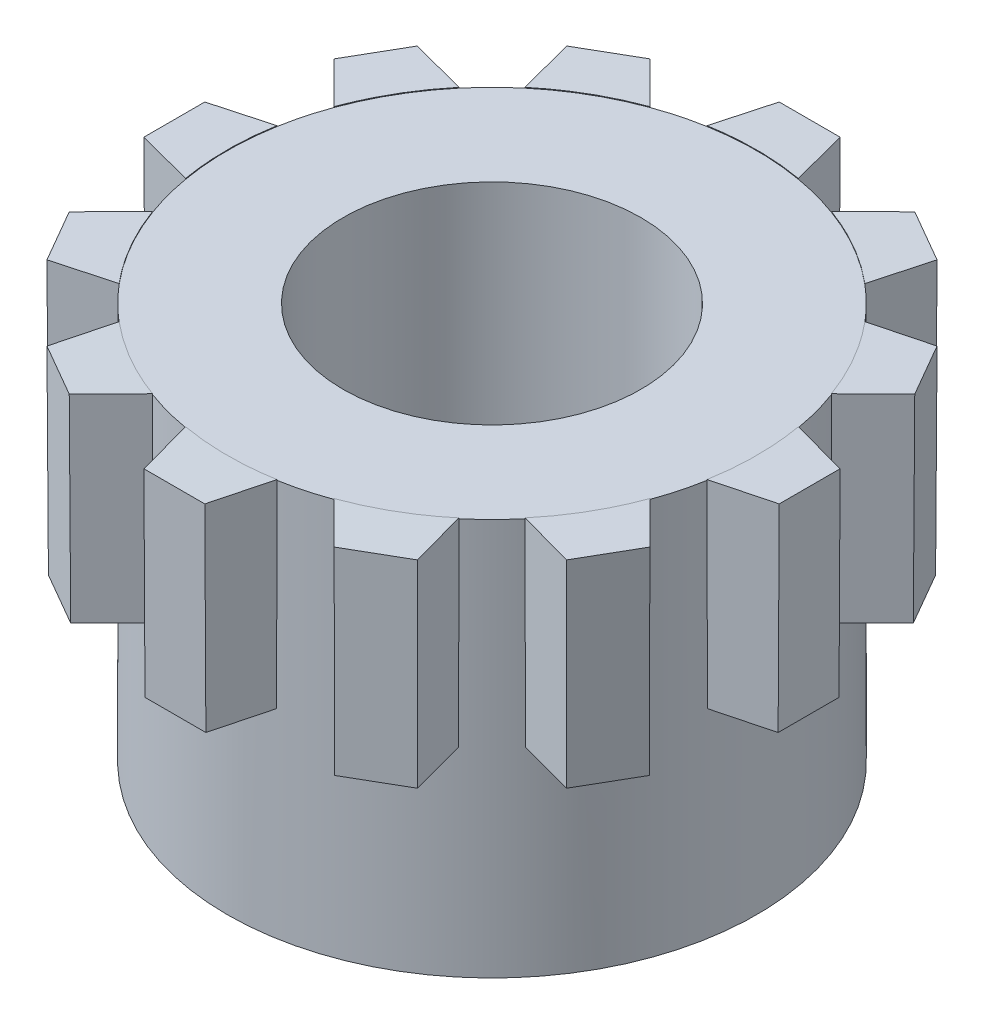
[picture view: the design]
ISO-10303-21;
HEADER;
FILE_DESCRIPTION(('STEP AP214'),'2;1');
FILE_NAME('part.step','',(''),(''),'','','');
FILE_SCHEMA(('AUTOMOTIVE_DESIGN { 1 0 10303 214 1 1 1 1 }'));
ENDSEC;
DATA;
#1=APPLICATION_CONTEXT('core data for automotive mechanical design processes');
#2=APPLICATION_PROTOCOL_DEFINITION('international standard','automotive_design',2000,#1);
#3=PRODUCT_CONTEXT('',#1,'mechanical');
#4=PRODUCT('Part','Part','',(#3));
#5=PRODUCT_RELATED_PRODUCT_CATEGORY('part','',(#4));
#6=PRODUCT_DEFINITION_FORMATION('','',#4);
#7=PRODUCT_DEFINITION_CONTEXT('part definition',#1,'design');
#8=PRODUCT_DEFINITION('design','',#6,#7);
#9=PRODUCT_DEFINITION_SHAPE('','',#8);
#10=(LENGTH_UNIT() NAMED_UNIT(*) SI_UNIT(.MILLI.,.METRE.));
#11=(NAMED_UNIT(*) PLANE_ANGLE_UNIT() SI_UNIT($,.RADIAN.));
#12=(NAMED_UNIT(*) SI_UNIT($,.STERADIAN.) SOLID_ANGLE_UNIT());
#13=UNCERTAINTY_MEASURE_WITH_UNIT(LENGTH_MEASURE(1.E-05),#10,'distance_accuracy_value','');
#14=(GEOMETRIC_REPRESENTATION_CONTEXT(3) GLOBAL_UNCERTAINTY_ASSIGNED_CONTEXT((#13)) GLOBAL_UNIT_ASSIGNED_CONTEXT((#10,
#11,#12)) REPRESENTATION_CONTEXT('',''));
#15=CARTESIAN_POINT('',(0.,0.,0.));
#16=DIRECTION('',(0.,0.,1.));
#17=DIRECTION('',(1.,0.,0.));
#18=AXIS2_PLACEMENT_3D('',#15,#16,#17);
#19=CARTESIAN_POINT('',(0.,0.,0.));
#20=DIRECTION('',(0.,-1.,0.));
#21=DIRECTION('',(0.,0.,-1.));
#22=AXIS2_PLACEMENT_3D('',#19,#20,#21);
#23=CYLINDRICAL_SURFACE('',#22,5.08);
#24=CARTESIAN_POINT('',(0.,0.,0.));
#25=DIRECTION('',(0.,-1.,0.));
#26=DIRECTION('',(0.,0.,-1.));
#27=AXIS2_PLACEMENT_3D('',#24,#25,#26);
#28=CIRCLE('',#27,5.08);
#29=CARTESIAN_POINT('',(0.,0.,-5.08));
#30=VERTEX_POINT('',#29);
#31=EDGE_CURVE('E884',#30,#30,#28,.T.);
#32=ORIENTED_EDGE('',*,*,#31,.F.);
#33=EDGE_LOOP('',(#32));
#34=FACE_BOUND('',#33,.T.);
#35=CARTESIAN_POINT('',(0.,7.62,0.));
#36=DIRECTION('',(0.,-1.,0.));
#37=DIRECTION('',(0.,0.,-1.));
#38=AXIS2_PLACEMENT_3D('',#35,#36,#37);
#39=CIRCLE('',#38,5.08);
#40=CARTESIAN_POINT('',(5.00374893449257,7.61999999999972,0.876867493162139));
#41=VERTEX_POINT('',#40);
#42=CARTESIAN_POINT('',(4.77180743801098,7.62,1.74248494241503));
#43=VERTEX_POINT('',#42);
#44=EDGE_CURVE('E891',#41,#43,#39,.T.);
#45=ORIENTED_EDGE('',*,*,#44,.T.);
#46=CARTESIAN_POINT('',(0.,-1525.31539035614,0.));
#47=DIRECTION('',(-0.70710351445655,0.0013973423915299,0.707108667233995));
#48=DIRECTION('',(-0.00098806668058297,-0.999999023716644,0.000988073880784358));
#49=AXIS2_PLACEMENT_3D('',#46,#47,#48);
#50=ELLIPSE('',#49,3635.47261629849,5.08);
#51=CARTESIAN_POINT('',(4.76979831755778,3.82406416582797,1.74797711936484));
#52=VERTEX_POINT('',#51);
#53=EDGE_CURVE('E50',#43,#52,#50,.F.);
#54=ORIENTED_EDGE('',*,*,#53,.T.);
#55=CARTESIAN_POINT('',(0.,3.85108481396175,0.));
#56=DIRECTION('',(0.00467559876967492,0.999985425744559,0.00269945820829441));
#57=DIRECTION('',(0.866012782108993,-0.00539891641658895,0.499992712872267));
#58=AXIS2_PLACEMENT_3D('',#55,#56,#57);
#59=ELLIPSE('',#58,5.08007403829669,5.08);
#60=CARTESIAN_POINT('',(3.89869174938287,3.82406416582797,3.25677795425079));
#61=VERTEX_POINT('',#60);
#62=EDGE_CURVE('E11',#52,#61,#59,.F.);
#63=ORIENTED_EDGE('',*,*,#62,.T.);
#64=CARTESIAN_POINT('',(0.,-1525.31539035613,0.));
#65=DIRECTION('',(-0.258822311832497,-0.00139734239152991,0.965923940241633));
#66=DIRECTION('',(0.000361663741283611,-0.999999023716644,-0.00134972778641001));
#67=AXIS2_PLACEMENT_3D('',#64,#65,#66);
#68=ELLIPSE('',#67,3635.47261629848,5.08);
#69=CARTESIAN_POINT('',(3.89493994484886,7.62,3.26126399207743));
#70=VERTEX_POINT('',#69);
#71=EDGE_CURVE('E941',#70,#61,#68,.F.);
#72=ORIENTED_EDGE('',*,*,#71,.F.);
#73=CARTESIAN_POINT('',(3.26126399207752,7.62,3.89493994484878));
#74=VERTEX_POINT('',#73);
#75=EDGE_CURVE('E892',#70,#74,#39,.T.);
#76=ORIENTED_EDGE('',*,*,#75,.T.);
#77=CARTESIAN_POINT('',(0.,-1525.31539035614,0.));
#78=DIRECTION('',(-0.965923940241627,0.0013973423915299,0.258822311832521));
#79=DIRECTION('',(-0.00134972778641,-0.999999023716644,0.000361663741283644));
#80=AXIS2_PLACEMENT_3D('',#77,#78,#79);
#81=ELLIPSE('',#80,3635.47261629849,5.08);
#82=CARTESIAN_POINT('',(3.25677795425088,3.82406416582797,3.89869174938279));
#83=VERTEX_POINT('',#82);
#84=EDGE_CURVE('E496',#74,#83,#81,.F.);
#85=ORIENTED_EDGE('',*,*,#84,.T.);
#86=CARTESIAN_POINT('',(0.,3.85108481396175,0.));
#87=DIRECTION('',(0.00269945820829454,0.999985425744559,0.00467559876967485));
#88=DIRECTION('',(0.499992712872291,-0.00539891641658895,0.866012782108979));
#89=AXIS2_PLACEMENT_3D('',#86,#87,#88);
#90=ELLIPSE('',#89,5.08007403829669,5.08);
#91=CARTESIAN_POINT('',(1.74797711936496,3.82406416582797,4.76979831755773));
#92=VERTEX_POINT('',#91);
#93=EDGE_CURVE('E40',#83,#92,#90,.F.);
#94=ORIENTED_EDGE('',*,*,#93,.T.);
#95=CARTESIAN_POINT('',(0.,-1525.31539035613,0.));
#96=DIRECTION('',(-0.707108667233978,-0.00139734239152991,0.707103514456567));
#97=DIRECTION('',(0.000988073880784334,-0.999999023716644,-0.000988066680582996));
#98=AXIS2_PLACEMENT_3D('',#95,#96,#97);
#99=ELLIPSE('',#98,3635.47261629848,5.08);
#100=CARTESIAN_POINT('',(1.74248494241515,7.62,4.77180743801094));
#101=VERTEX_POINT('',#100);
#102=EDGE_CURVE('E487',#101,#92,#99,.F.);
#103=ORIENTED_EDGE('',*,*,#102,.F.);
#104=CARTESIAN_POINT('',(0.876867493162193,7.62,5.00374893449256));
#105=VERTEX_POINT('',#104);
#106=EDGE_CURVE('E1052',#101,#105,#39,.T.);
#107=ORIENTED_EDGE('',*,*,#106,.T.);
#108=CARTESIAN_POINT('',(0.,-1525.31539035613,0.));
#109=DIRECTION('',(-0.965925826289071,0.0013973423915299,-0.258815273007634));
#110=DIRECTION('',(-0.00134973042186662,-0.999999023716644,-0.000361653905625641));
#111=AXIS2_PLACEMENT_3D('',#108,#109,#110);
#112=ELLIPSE('',#111,3635.47261629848,5.08);
#113=CARTESIAN_POINT('',(0.87110656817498,3.82406416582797,5.00475507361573));
#114=VERTEX_POINT('',#113);
#115=EDGE_CURVE('E1558',#105,#114,#112,.F.);
#116=ORIENTED_EDGE('',*,*,#115,.T.);
#117=CARTESIAN_POINT('',(0.,3.85108481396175,0.));
#118=DIRECTION('',(0.,0.999985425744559,0.00539891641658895));
#119=DIRECTION('',(0.,-0.00539891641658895,0.999985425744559));
#120=AXIS2_PLACEMENT_3D('',#117,#118,#119);
#121=ELLIPSE('',#120,5.08007403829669,5.08);
#122=CARTESIAN_POINT('',(-0.871106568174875,3.82406416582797,5.00475507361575));
#123=VERTEX_POINT('',#122);
#124=EDGE_CURVE('E917',#114,#123,#121,.F.);
#125=ORIENTED_EDGE('',*,*,#124,.T.);
#126=CARTESIAN_POINT('',(0.,-1525.31539035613,0.));
#127=DIRECTION('',(-0.965925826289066,-0.0013973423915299,0.258815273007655));
#128=DIRECTION('',(0.00134973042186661,-0.999999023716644,-0.00036165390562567));
#129=AXIS2_PLACEMENT_3D('',#126,#127,#128);
#130=ELLIPSE('',#129,3635.47261629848,5.08);
#131=CARTESIAN_POINT('',(-0.876867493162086,7.62,5.00374893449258));
#132=VERTEX_POINT('',#131);
#133=EDGE_CURVE('E1551',#132,#123,#130,.F.);
#134=ORIENTED_EDGE('',*,*,#133,.F.);
#135=CARTESIAN_POINT('',(-1.74248494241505,7.62,4.77180743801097));
#136=VERTEX_POINT('',#135);
#137=EDGE_CURVE('E1056',#132,#136,#39,.T.);
#138=ORIENTED_EDGE('',*,*,#137,.T.);
#139=CARTESIAN_POINT('',(0.,-1525.31539035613,0.));
#140=DIRECTION('',(-0.707108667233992,0.0013973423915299,-0.707103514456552));
#141=DIRECTION('',(-0.000988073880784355,-0.999999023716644,-0.000988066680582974));
#142=AXIS2_PLACEMENT_3D('',#139,#140,#141);
#143=ELLIPSE('',#142,3635.47261629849,5.08);
#144=CARTESIAN_POINT('',(-1.74797711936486,3.82406416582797,4.76979831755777));
#145=VERTEX_POINT('',#144);
#146=EDGE_CURVE('E573',#136,#145,#143,.F.);
#147=ORIENTED_EDGE('',*,*,#146,.T.);
#148=CARTESIAN_POINT('',(0.,3.85108481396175,0.));
#149=DIRECTION('',(-0.00269945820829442,0.999985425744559,0.00467559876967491));
#150=DIRECTION('',(-0.49999271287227,-0.00539891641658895,0.866012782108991));
#151=AXIS2_PLACEMENT_3D('',#148,#149,#150);
#152=ELLIPSE('',#151,5.08007403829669,5.08);
#153=CARTESIAN_POINT('',(-3.2567779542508,3.82406416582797,3.89869174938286));
#154=VERTEX_POINT('',#153);
#155=EDGE_CURVE('E915',#145,#154,#152,.F.);
#156=ORIENTED_EDGE('',*,*,#155,.T.);
#157=CARTESIAN_POINT('',(0.,-1525.31539035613,0.));
#158=DIRECTION('',(-0.965923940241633,-0.0013973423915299,-0.2588223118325));
#159=DIRECTION('',(0.00134972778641,-0.999999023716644,0.000361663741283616));
#160=AXIS2_PLACEMENT_3D('',#157,#158,#159);
#161=ELLIPSE('',#160,3635.47261629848,5.08);
#162=CARTESIAN_POINT('',(-3.26126399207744,7.62,3.89493994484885));
#163=VERTEX_POINT('',#162);
#164=EDGE_CURVE('E564',#163,#154,#161,.F.);
#165=ORIENTED_EDGE('',*,*,#164,.F.);
#166=CARTESIAN_POINT('',(-3.89493994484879,7.62,3.26126399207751));
#167=VERTEX_POINT('',#166);
#168=EDGE_CURVE('E1058',#163,#167,#39,.T.);
#169=ORIENTED_EDGE('',*,*,#168,.T.);
#170=CARTESIAN_POINT('',(0.,-1525.31539035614,0.));
#171=DIRECTION('',(-0.258822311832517,0.0013973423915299,-0.965923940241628));
#172=DIRECTION('',(-0.000361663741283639,-0.999999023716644,-0.00134972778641));
#173=AXIS2_PLACEMENT_3D('',#170,#171,#172);
#174=ELLIPSE('',#173,3635.47261629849,5.08);
#175=CARTESIAN_POINT('',(-3.8986917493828,3.82406416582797,3.25677795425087));
#176=VERTEX_POINT('',#175);
#177=EDGE_CURVE('E1586',#167,#176,#174,.F.);
#178=ORIENTED_EDGE('',*,*,#177,.T.);
#179=CARTESIAN_POINT('',(0.,3.85108481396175,0.));
#180=DIRECTION('',(-0.00467559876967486,0.999985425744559,0.00269945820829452));
#181=DIRECTION('',(-0.86601278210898,-0.00539891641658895,0.499992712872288));
#182=AXIS2_PLACEMENT_3D('',#179,#180,#181);
#183=ELLIPSE('',#182,5.08007403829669,5.08);
#184=CARTESIAN_POINT('',(-4.76979831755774,3.82406416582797,1.74797711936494));
#185=VERTEX_POINT('',#184);
#186=EDGE_CURVE('E913',#176,#185,#183,.F.);
#187=ORIENTED_EDGE('',*,*,#186,.T.);
#188=CARTESIAN_POINT('',(0.,-1525.31539035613,0.));
#189=DIRECTION('',(-0.707103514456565,-0.00139734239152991,-0.70710866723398));
#190=DIRECTION('',(0.000988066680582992,-0.999999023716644,0.000988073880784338));
#191=AXIS2_PLACEMENT_3D('',#188,#189,#190);
#192=ELLIPSE('',#191,3635.47261629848,5.08);
#193=CARTESIAN_POINT('',(-4.77180743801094,7.62,1.74248494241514));
#194=VERTEX_POINT('',#193);
#195=EDGE_CURVE('E1593',#194,#185,#192,.F.);
#196=ORIENTED_EDGE('',*,*,#195,.F.);
#197=CARTESIAN_POINT('',(-5.00374893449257,7.62,0.876867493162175));
#198=VERTEX_POINT('',#197);
#199=EDGE_CURVE('E1066',#194,#198,#39,.T.);
#200=ORIENTED_EDGE('',*,*,#199,.T.);
#201=CARTESIAN_POINT('',(0.,-1525.31539035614,0.));
#202=DIRECTION('',(0.258815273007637,0.0013973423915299,-0.96592582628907));
#203=DIRECTION('',(0.000361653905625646,-0.999999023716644,-0.00134973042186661));
#204=AXIS2_PLACEMENT_3D('',#201,#202,#203);
#205=ELLIPSE('',#204,3635.47261629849,5.08);
#206=CARTESIAN_POINT('',(-5.00475507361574,3.82406416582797,0.871106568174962));
#207=VERTEX_POINT('',#206);
#208=EDGE_CURVE('E650',#198,#207,#205,.F.);
#209=ORIENTED_EDGE('',*,*,#208,.T.);
#210=CARTESIAN_POINT('',(0.,3.85108481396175,0.));
#211=DIRECTION('',(-0.00539891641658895,0.999985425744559,0.));
#212=DIRECTION('',(-0.999985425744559,-0.00539891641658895,0.));
#213=AXIS2_PLACEMENT_3D('',#210,#211,#212);
#214=ELLIPSE('',#213,5.08007403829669,5.08);
#215=CARTESIAN_POINT('',(-5.00475507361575,3.82406416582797,-0.871106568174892));
#216=VERTEX_POINT('',#215);
#217=EDGE_CURVE('E911',#207,#216,#214,.F.);
#218=ORIENTED_EDGE('',*,*,#217,.T.);
#219=CARTESIAN_POINT('',(0.,-1525.31539035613,0.));
#220=DIRECTION('',(-0.258815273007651,-0.0013973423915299,-0.965925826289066));
#221=DIRECTION('',(0.000361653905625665,-0.999999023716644,0.00134973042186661));
#222=AXIS2_PLACEMENT_3D('',#219,#220,#221);
#223=ELLIPSE('',#222,3635.47261629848,5.08);
#224=CARTESIAN_POINT('',(-5.00374893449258,7.62,-0.876867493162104));
#225=VERTEX_POINT('',#224);
#226=EDGE_CURVE('E641',#225,#216,#223,.F.);
#227=ORIENTED_EDGE('',*,*,#226,.F.);
#228=CARTESIAN_POINT('',(-4.77180743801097,7.62,-1.74248494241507));
#229=VERTEX_POINT('',#228);
#230=EDGE_CURVE('E1068',#225,#229,#39,.T.);
#231=ORIENTED_EDGE('',*,*,#230,.T.);
#232=CARTESIAN_POINT('',(0.,-1525.31539035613,0.));
#233=DIRECTION('',(0.707103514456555,0.0013973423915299,-0.70710866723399));
#234=DIRECTION('',(0.000988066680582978,-0.999999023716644,-0.000988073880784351));
#235=AXIS2_PLACEMENT_3D('',#232,#233,#234);
#236=ELLIPSE('',#235,3635.47261629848,5.08);
#237=CARTESIAN_POINT('',(-4.76979831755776,3.82406416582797,-1.74797711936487));
#238=VERTEX_POINT('',#237);
#239=EDGE_CURVE('E1631',#229,#238,#236,.F.);
#240=ORIENTED_EDGE('',*,*,#239,.T.);
#241=CARTESIAN_POINT('',(0.,3.85108481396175,0.));
#242=DIRECTION('',(-0.0046755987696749,0.999985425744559,-0.00269945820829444));
#243=DIRECTION('',(-0.866012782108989,-0.00539891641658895,-0.499992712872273));
#244=AXIS2_PLACEMENT_3D('',#241,#242,#243);
#245=ELLIPSE('',#244,5.08007403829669,5.08);
#246=CARTESIAN_POINT('',(-3.89869174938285,3.82406416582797,-3.25677795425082));
#247=VERTEX_POINT('',#246);
#248=EDGE_CURVE('E909',#238,#247,#245,.F.);
#249=ORIENTED_EDGE('',*,*,#248,.T.);
#250=CARTESIAN_POINT('',(0.,-1525.31539035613,0.));
#251=DIRECTION('',(0.258822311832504,-0.0013973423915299,-0.965923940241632));
#252=DIRECTION('',(-0.00036166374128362,-0.999999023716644,0.00134972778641));
#253=AXIS2_PLACEMENT_3D('',#250,#251,#252);
#254=ELLIPSE('',#253,3635.47261629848,5.08);
#255=CARTESIAN_POINT('',(-3.89493994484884,7.62,-3.26126399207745));
#256=VERTEX_POINT('',#255);
#257=EDGE_CURVE('E1638',#256,#247,#254,.F.);
#258=ORIENTED_EDGE('',*,*,#257,.F.);
#259=CARTESIAN_POINT('',(-3.2612639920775,7.62,-3.8949399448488));
#260=VERTEX_POINT('',#259);
#261=EDGE_CURVE('E1076',#256,#260,#39,.T.);
#262=ORIENTED_EDGE('',*,*,#261,.T.);
#263=CARTESIAN_POINT('',(0.,-1525.31539035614,0.));
#264=DIRECTION('',(0.965923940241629,0.0013973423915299,-0.258822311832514));
#265=DIRECTION('',(0.00134972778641,-0.999999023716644,-0.000361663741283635));
#266=AXIS2_PLACEMENT_3D('',#263,#264,#265);
#267=ELLIPSE('',#266,3635.47261629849,5.08);
#268=CARTESIAN_POINT('',(-3.25677795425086,3.82406416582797,-3.89869174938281));
#269=VERTEX_POINT('',#268);
#270=EDGE_CURVE('E727',#260,#269,#267,.F.);
#271=ORIENTED_EDGE('',*,*,#270,.T.);
#272=CARTESIAN_POINT('',(0.,3.85108481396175,0.));
#273=DIRECTION('',(-0.00269945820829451,0.999985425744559,-0.00467559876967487));
#274=DIRECTION('',(-0.499992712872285,-0.00539891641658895,-0.866012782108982));
#275=AXIS2_PLACEMENT_3D('',#272,#273,#274);
#276=ELLIPSE('',#275,5.08007403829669,5.08);
#277=CARTESIAN_POINT('',(-1.74797711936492,3.82406416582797,-4.76979831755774));
#278=VERTEX_POINT('',#277);
#279=EDGE_CURVE('E907',#269,#278,#276,.F.);
#280=ORIENTED_EDGE('',*,*,#279,.T.);
#281=CARTESIAN_POINT('',(0.,-1525.31539035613,0.));
#282=DIRECTION('',(0.707108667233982,-0.00139734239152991,-0.707103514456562));
#283=DIRECTION('',(-0.000988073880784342,-0.999999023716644,0.000988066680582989));
#284=AXIS2_PLACEMENT_3D('',#281,#282,#283);
#285=ELLIPSE('',#284,3635.47261629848,5.08);
#286=CARTESIAN_POINT('',(-1.74248494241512,7.62,-4.77180743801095));
#287=VERTEX_POINT('',#286);
#288=EDGE_CURVE('E718',#287,#278,#285,.F.);
#289=ORIENTED_EDGE('',*,*,#288,.F.);
#290=CARTESIAN_POINT('',(-0.876867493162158,7.62,-5.00374893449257));
#291=VERTEX_POINT('',#290);
#292=EDGE_CURVE('E1078',#287,#291,#39,.T.);
#293=ORIENTED_EDGE('',*,*,#292,.T.);
#294=CARTESIAN_POINT('',(0.,-1525.31539035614,0.));
#295=DIRECTION('',(0.965925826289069,0.0013973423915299,0.258815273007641));
#296=DIRECTION('',(0.00134973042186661,-0.999999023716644,0.000361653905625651));
#297=AXIS2_PLACEMENT_3D('',#294,#295,#296);
#298=ELLIPSE('',#297,3635.47261629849,5.08);
#299=CARTESIAN_POINT('',(-0.871106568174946,3.82406416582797,-5.00475507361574));
#300=VERTEX_POINT('',#299);
#301=EDGE_CURVE('E1107',#291,#300,#298,.F.);
#302=ORIENTED_EDGE('',*,*,#301,.T.);
#303=CARTESIAN_POINT('',(0.,3.85108481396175,0.));
#304=DIRECTION('',(0.,0.999985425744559,-0.00539891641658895));
#305=DIRECTION('',(0.,-0.00539891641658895,-0.999985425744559));
#306=AXIS2_PLACEMENT_3D('',#303,#304,#305);
#307=ELLIPSE('',#306,5.08007403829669,5.08);
#308=CARTESIAN_POINT('',(0.871106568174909,3.82406416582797,-5.00475507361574));
#309=VERTEX_POINT('',#308);
#310=EDGE_CURVE('E905',#300,#309,#307,.F.);
#311=ORIENTED_EDGE('',*,*,#310,.T.);
#312=CARTESIAN_POINT('',(0.,-1525.31539035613,0.));
#313=DIRECTION('',(0.965925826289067,-0.0013973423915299,-0.258815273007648));
#314=DIRECTION('',(-0.00134973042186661,-0.999999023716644,0.00036165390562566));
#315=AXIS2_PLACEMENT_3D('',#312,#313,#314);
#316=ELLIPSE('',#315,3635.47261629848,5.08);
#317=CARTESIAN_POINT('',(0.876867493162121,7.62,-5.00374893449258));
#318=VERTEX_POINT('',#317);
#319=EDGE_CURVE('E1111',#318,#309,#316,.F.);
#320=ORIENTED_EDGE('',*,*,#319,.F.);
#321=CARTESIAN_POINT('',(1.74248494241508,7.62,-4.77180743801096));
#322=VERTEX_POINT('',#321);
#323=EDGE_CURVE('E1085',#318,#322,#39,.T.);
#324=ORIENTED_EDGE('',*,*,#323,.T.);
#325=CARTESIAN_POINT('',(0.,-1525.31539035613,0.));
#326=DIRECTION('',(0.707108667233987,0.0013973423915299,0.707103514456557));
#327=DIRECTION('',(0.000988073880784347,-0.999999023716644,0.000988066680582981));
#328=AXIS2_PLACEMENT_3D('',#325,#326,#327);
#329=ELLIPSE('',#328,3635.47261629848,5.08);
#330=CARTESIAN_POINT('',(1.74797711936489,3.82406416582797,-4.76979831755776));
#331=VERTEX_POINT('',#330);
#332=EDGE_CURVE('E804',#322,#331,#329,.F.);
#333=ORIENTED_EDGE('',*,*,#332,.T.);
#334=CARTESIAN_POINT('',(0.,3.85108481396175,0.));
#335=DIRECTION('',(0.00269945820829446,0.999985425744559,-0.00467559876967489));
#336=DIRECTION('',(0.499992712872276,-0.00539891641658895,-0.866012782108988));
#337=AXIS2_PLACEMENT_3D('',#334,#335,#336);
#338=ELLIPSE('',#337,5.08007403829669,5.08);
#339=CARTESIAN_POINT('',(3.25677795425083,3.82406416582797,-3.89869174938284));
#340=VERTEX_POINT('',#339);
#341=EDGE_CURVE('E903',#331,#340,#338,.F.);
#342=ORIENTED_EDGE('',*,*,#341,.T.);
#343=CARTESIAN_POINT('',(0.,-1525.31539035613,0.));
#344=DIRECTION('',(0.965923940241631,-0.0013973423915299,0.258822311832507));
#345=DIRECTION('',(-0.00134972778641,-0.999999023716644,-0.000361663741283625));
#346=AXIS2_PLACEMENT_3D('',#343,#344,#345);
#347=ELLIPSE('',#346,3635.47261629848,5.08);
#348=CARTESIAN_POINT('',(3.26126399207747,7.62,-3.89493994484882));
#349=VERTEX_POINT('',#348);
#350=EDGE_CURVE('E795',#349,#340,#347,.F.);
#351=ORIENTED_EDGE('',*,*,#350,.F.);
#352=CARTESIAN_POINT('',(3.89493994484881,7.62,-3.26126399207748));
#353=VERTEX_POINT('',#352);
#354=EDGE_CURVE('E1049',#349,#353,#39,.T.);
#355=ORIENTED_EDGE('',*,*,#354,.T.);
#356=CARTESIAN_POINT('',(0.,-1525.31539035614,0.));
#357=DIRECTION('',(0.25882231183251,0.0013973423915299,0.96592394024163));
#358=DIRECTION('',(0.00036166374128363,-0.999999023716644,0.00134972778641));
#359=AXIS2_PLACEMENT_3D('',#356,#357,#358);
#360=ELLIPSE('',#359,3635.47261629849,5.08);
#361=CARTESIAN_POINT('',(3.89869174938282,3.82406416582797,-3.25677795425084));
#362=VERTEX_POINT('',#361);
#363=EDGE_CURVE('E1008',#353,#362,#360,.F.);
#364=ORIENTED_EDGE('',*,*,#363,.T.);
#365=CARTESIAN_POINT('',(0.,3.85108481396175,0.));
#366=DIRECTION('',(0.00467559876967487,0.999985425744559,-0.00269945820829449));
#367=DIRECTION('',(0.866012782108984,-0.00539891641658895,-0.499992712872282));
#368=AXIS2_PLACEMENT_3D('',#365,#366,#367);
#369=ELLIPSE('',#368,5.08007403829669,5.08);
#370=CARTESIAN_POINT('',(4.76979831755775,3.82406416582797,-1.74797711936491));
#371=VERTEX_POINT('',#370);
#372=EDGE_CURVE('E901',#362,#371,#369,.F.);
#373=ORIENTED_EDGE('',*,*,#372,.T.);
#374=CARTESIAN_POINT('',(0.,-1525.31539035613,0.));
#375=DIRECTION('',(0.70710351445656,-0.0013973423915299,0.707108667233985));
#376=DIRECTION('',(-0.000988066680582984,-0.999999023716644,-0.000988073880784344));
#377=AXIS2_PLACEMENT_3D('',#374,#375,#376);
#378=ELLIPSE('',#377,3635.47261629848,5.08);
#379=CARTESIAN_POINT('',(4.77180743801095,7.62,-1.7424849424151));
#380=VERTEX_POINT('',#379);
#381=EDGE_CURVE('E1012',#380,#371,#378,.F.);
#382=ORIENTED_EDGE('',*,*,#381,.F.);
#383=CARTESIAN_POINT('',(5.00374893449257,7.61999999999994,-0.87686749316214));
#384=VERTEX_POINT('',#383);
#385=EDGE_CURVE('E887',#380,#384,#39,.T.);
#386=ORIENTED_EDGE('',*,*,#385,.T.);
#387=CARTESIAN_POINT('',(0.,-1525.31539035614,0.));
#388=DIRECTION('',(-0.258815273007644,0.0013973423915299,0.965925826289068));
#389=DIRECTION('',(-0.000361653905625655,-0.999999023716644,0.00134973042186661));
#390=AXIS2_PLACEMENT_3D('',#387,#388,#389);
#391=ELLIPSE('',#390,3635.47261629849,5.08);
#392=CARTESIAN_POINT('',(5.00475507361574,3.82406416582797,-0.871106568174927));
#393=VERTEX_POINT('',#392);
#394=EDGE_CURVE('E898',#384,#393,#391,.F.);
#395=ORIENTED_EDGE('',*,*,#394,.T.);
#396=CARTESIAN_POINT('',(0.,3.85108481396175,0.));
#397=DIRECTION('',(0.00539891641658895,0.999985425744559,0.));
#398=DIRECTION('',(0.999985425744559,-0.00539891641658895,0.));
#399=AXIS2_PLACEMENT_3D('',#396,#397,#398);
#400=ELLIPSE('',#399,5.08007403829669,5.08);
#401=CARTESIAN_POINT('',(5.00475507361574,3.82406416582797,0.871106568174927));
#402=VERTEX_POINT('',#401);
#403=EDGE_CURVE('E890',#393,#402,#400,.F.);
#404=ORIENTED_EDGE('',*,*,#403,.T.);
#405=CARTESIAN_POINT('',(0.,-1525.31539035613,0.));
#406=DIRECTION('',(0.258815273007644,-0.0013973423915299,0.965925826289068));
#407=DIRECTION('',(-0.000361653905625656,-0.999999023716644,-0.00134973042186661));
#408=AXIS2_PLACEMENT_3D('',#405,#406,#407);
#409=ELLIPSE('',#408,3635.47261629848,5.08);
#410=EDGE_CURVE('E895',#41,#402,#409,.F.);
#411=ORIENTED_EDGE('',*,*,#410,.F.);
#412=EDGE_LOOP('',(#45,#54,#63,#72,#76,#85,#94,#103,#107,#116,#125,#134,#138,#147,#156,#165,
#169,#178,#187,#196,#200,#209,#218,#227,#231,#240,#249,#258,#262,#271,#280,#289,#293,#302,#311,
#320,#324,#333,#342,#351,#355,#364,#373,#382,#386,#395,#404,#411));
#413=FACE_BOUND('',#412,.T.);
#414=ADVANCED_FACE('F32',(#34,#413),#23,.T.);
#415=CARTESIAN_POINT('',(2.8575,7.62,0.));
#416=DIRECTION('',(0.,1.,0.));
#417=DIRECTION('',(0.,0.,1.));
#418=AXIS2_PLACEMENT_3D('',#415,#416,#417);
#419=PLANE('',#418);
#420=CARTESIAN_POINT('',(0.,7.62,0.));
#421=DIRECTION('',(0.,-1.,0.));
#422=DIRECTION('',(0.,0.,-1.));
#423=AXIS2_PLACEMENT_3D('',#420,#421,#422);
#424=CIRCLE('',#423,2.8575);
#425=CARTESIAN_POINT('',(0.,7.62,-2.8575));
#426=VERTEX_POINT('',#425);
#427=EDGE_CURVE('E872',#426,#426,#424,.T.);
#428=ORIENTED_EDGE('',*,*,#427,.T.);
#429=EDGE_LOOP('',(#428));
#430=FACE_BOUND('',#429,.T.);
#431=EDGE_CURVE('E888',#384,#41,#39,.T.);
#432=ORIENTED_EDGE('',*,*,#431,.F.);
#433=ORIENTED_EDGE('',*,*,#385,.F.);
#434=EDGE_CURVE('E1048',#353,#380,#39,.T.);
#435=ORIENTED_EDGE('',*,*,#434,.F.);
#436=ORIENTED_EDGE('',*,*,#354,.F.);
#437=EDGE_CURVE('E1050',#322,#349,#39,.T.);
#438=ORIENTED_EDGE('',*,*,#437,.F.);
#439=ORIENTED_EDGE('',*,*,#323,.F.);
#440=EDGE_CURVE('E1051',#291,#318,#39,.T.);
#441=ORIENTED_EDGE('',*,*,#440,.F.);
#442=ORIENTED_EDGE('',*,*,#292,.F.);
#443=EDGE_CURVE('E1081',#260,#287,#39,.T.);
#444=ORIENTED_EDGE('',*,*,#443,.F.);
#445=ORIENTED_EDGE('',*,*,#261,.F.);
#446=EDGE_CURVE('E1072',#229,#256,#39,.T.);
#447=ORIENTED_EDGE('',*,*,#446,.F.);
#448=ORIENTED_EDGE('',*,*,#230,.F.);
#449=EDGE_CURVE('E1071',#198,#225,#39,.T.);
#450=ORIENTED_EDGE('',*,*,#449,.F.);
#451=ORIENTED_EDGE('',*,*,#199,.F.);
#452=EDGE_CURVE('E1062',#167,#194,#39,.T.);
#453=ORIENTED_EDGE('',*,*,#452,.F.);
#454=ORIENTED_EDGE('',*,*,#168,.F.);
#455=EDGE_CURVE('E1061',#136,#163,#39,.T.);
#456=ORIENTED_EDGE('',*,*,#455,.F.);
#457=ORIENTED_EDGE('',*,*,#137,.F.);
#458=EDGE_CURVE('E1054',#105,#132,#39,.T.);
#459=ORIENTED_EDGE('',*,*,#458,.F.);
#460=ORIENTED_EDGE('',*,*,#106,.F.);
#461=EDGE_CURVE('E1053',#74,#101,#39,.T.);
#462=ORIENTED_EDGE('',*,*,#461,.F.);
#463=ORIENTED_EDGE('',*,*,#75,.F.);
#464=EDGE_CURVE('E413',#43,#70,#39,.T.);
#465=ORIENTED_EDGE('',*,*,#464,.F.);
#466=ORIENTED_EDGE('',*,*,#44,.F.);
#467=EDGE_LOOP('',(#432,#433,#435,#436,#438,#439,#441,#442,#444,#445,#447,#448,#450,#451,#453,
#454,#456,#457,#459,#460,#462,#463,#465,#466));
#468=FACE_BOUND('',#467,.T.);
#469=ADVANCED_FACE('F34',(#430,#468),#419,.T.);
#470=CARTESIAN_POINT('',(2.8575,0.,0.));
#471=DIRECTION('',(0.,-1.,0.));
#472=DIRECTION('',(0.,0.,-1.));
#473=AXIS2_PLACEMENT_3D('',#470,#471,#472);
#474=PLANE('',#473);
#475=ORIENTED_EDGE('',*,*,#31,.T.);
#476=EDGE_LOOP('',(#475));
#477=FACE_BOUND('',#476,.T.);
#478=CARTESIAN_POINT('',(0.,0.,0.));
#479=DIRECTION('',(0.,-1.,0.));
#480=DIRECTION('',(0.,0.,-1.));
#481=AXIS2_PLACEMENT_3D('',#478,#479,#480);
#482=CIRCLE('',#481,2.8575);
#483=CARTESIAN_POINT('',(0.,0.,-2.8575));
#484=VERTEX_POINT('',#483);
#485=EDGE_CURVE('E881',#484,#484,#482,.T.);
#486=ORIENTED_EDGE('',*,*,#485,.F.);
#487=EDGE_LOOP('',(#486));
#488=FACE_BOUND('',#487,.T.);
#489=ADVANCED_FACE('F971',(#477,#488),#474,.T.);
#490=CARTESIAN_POINT('',(0.,0.,0.));
#491=DIRECTION('',(0.,-1.,0.));
#492=DIRECTION('',(0.,0.,-1.));
#493=AXIS2_PLACEMENT_3D('',#490,#491,#492);
#494=CYLINDRICAL_SURFACE('',#493,2.8575);
#495=ORIENTED_EDGE('',*,*,#485,.T.);
#496=EDGE_LOOP('',(#495));
#497=FACE_BOUND('',#496,.T.);
#498=ORIENTED_EDGE('',*,*,#427,.F.);
#499=EDGE_LOOP('',(#498));
#500=FACE_BOUND('',#499,.T.);
#501=ADVANCED_FACE('F854',(#497,#500),#494,.F.);
#502=CARTESIAN_POINT('',(-0.0203477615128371,3.85119467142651,0.));
#503=DIRECTION('',(0.00539891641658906,0.999985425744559,0.));
#504=DIRECTION('',(0.,0.,1.));
#505=AXIS2_PLACEMENT_3D('',#502,#503,#504);
#506=ELLIPSE('',#505,5.08,5.07992596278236);
#507=DIRECTION('',(0.00539891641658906,0.999985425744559,0.));
#508=VECTOR('',#507,1.);
#509=SURFACE_OF_LINEAR_EXTRUSION('',#506,#508);
#510=ORIENTED_EDGE('',*,*,#431,.T.);
#511=DIRECTION('',(0.00539891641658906,0.999985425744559,0.));
#512=VECTOR('',#511,1.);
#513=CARTESIAN_POINT('',(4.98325532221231,3.82418024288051,0.876867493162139));
#514=LINE('',#513,#512);
#515=CARTESIAN_POINT('',(5.00382519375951,7.63412471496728,0.876867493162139));
#516=VERTEX_POINT('',#515);
#517=EDGE_CURVE('E869',#41,#516,#514,.T.);
#518=ORIENTED_EDGE('',*,*,#517,.T.);
#519=CARTESIAN_POINT('',(0.000222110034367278,7.66113914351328,0.));
#520=DIRECTION('',(0.00539891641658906,0.999985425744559,0.));
#521=DIRECTION('',(0.,0.,1.));
#522=AXIS2_PLACEMENT_3D('',#519,#520,#521);
#523=ELLIPSE('',#522,5.08,5.07992596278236);
#524=CARTESIAN_POINT('',(5.00382519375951,7.63412471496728,-0.87686749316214));
#525=VERTEX_POINT('',#524);
#526=EDGE_CURVE('E1006',#516,#525,#523,.T.);
#527=ORIENTED_EDGE('',*,*,#526,.T.);
#528=DIRECTION('',(0.00539891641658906,0.999985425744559,0.));
#529=VECTOR('',#528,1.);
#530=CARTESIAN_POINT('',(4.98325532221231,3.82418024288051,-0.87686749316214));
#531=LINE('',#530,#529);
#532=EDGE_CURVE('E870',#384,#525,#531,.T.);
#533=ORIENTED_EDGE('',*,*,#532,.F.);
#534=EDGE_LOOP('',(#510,#518,#527,#533));
#535=FACE_BOUND('',#534,.T.);
#536=ADVANCED_FACE('F843',(#535),#509,.F.);
#537=CARTESIAN_POINT('',(4.08071570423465,3.82905304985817,-1.11870577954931));
#538=DIRECTION('',(-0.258815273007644,0.0013973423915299,0.965925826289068));
#539=DIRECTION('',(0.965926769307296,0.,0.258815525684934));
#540=AXIS2_PLACEMENT_3D('',#537,#538,#539);
#541=PLANE('',#540);
#542=ORIENTED_EDGE('',*,*,#394,.F.);
#543=ORIENTED_EDGE('',*,*,#532,.T.);
#544=DIRECTION('',(0.965911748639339,-0.0052149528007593,0.258819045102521));
#545=VECTOR('',#544,1.);
#546=CARTESIAN_POINT('',(4.10128557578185,7.63899752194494,-1.11870577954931));
#547=LINE('',#546,#545);
#548=CARTESIAN_POINT('',(6.09605922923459,7.62822774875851,-0.584200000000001));
#549=VERTEX_POINT('',#548);
#550=EDGE_CURVE('E860',#525,#549,#547,.T.);
#551=ORIENTED_EDGE('',*,*,#550,.T.);
#552=DIRECTION('',(0.00539891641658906,0.999985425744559,0.));
#553=VECTOR('',#552,1.);
#554=CARTESIAN_POINT('',(6.07548935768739,3.81828327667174,-0.584200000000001));
#555=LINE('',#554,#553);
#556=CARTESIAN_POINT('',(6.07548935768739,3.81828327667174,-0.584200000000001));
#557=VERTEX_POINT('',#556);
#558=EDGE_CURVE('E873',#557,#549,#555,.T.);
#559=ORIENTED_EDGE('',*,*,#558,.F.);
#560=DIRECTION('',(0.965911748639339,-0.0052149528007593,0.258819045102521));
#561=VECTOR('',#560,1.);
#562=CARTESIAN_POINT('',(4.08071570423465,3.82905304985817,-1.11870577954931));
#563=LINE('',#562,#561);
#564=EDGE_CURVE('E867',#393,#557,#563,.T.);
#565=ORIENTED_EDGE('',*,*,#564,.F.);
#566=EDGE_LOOP('',(#542,#543,#551,#559,#565));
#567=FACE_BOUND('',#566,.T.);
#568=ADVANCED_FACE('F839',(#567),#541,.F.);
#569=CARTESIAN_POINT('',(6.07548935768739,3.81828327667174,1.27411800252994E-05));
#570=DIRECTION('',(-0.999985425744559,0.00539891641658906,0.));
#571=DIRECTION('',(-0.00539891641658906,-0.999985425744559,0.));
#572=AXIS2_PLACEMENT_3D('',#569,#570,#571);
#573=PLANE('',#572);
#574=DIRECTION('',(0.,0.,1.));
#575=VECTOR('',#574,1.);
#576=CARTESIAN_POINT('',(6.0960592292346,7.62822774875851,1.27411800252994E-05));
#577=LINE('',#576,#575);
#578=CARTESIAN_POINT('',(6.0960592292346,7.62822774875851,0.584199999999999));
#579=VERTEX_POINT('',#578);
#580=EDGE_CURVE('E1005',#549,#579,#577,.T.);
#581=ORIENTED_EDGE('',*,*,#580,.T.);
#582=DIRECTION('',(0.00539891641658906,0.999985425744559,0.));
#583=VECTOR('',#582,1.);
#584=CARTESIAN_POINT('',(6.07548935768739,3.81828327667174,0.584199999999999));
#585=LINE('',#584,#583);
#586=CARTESIAN_POINT('',(6.07548935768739,3.81828327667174,0.584199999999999));
#587=VERTEX_POINT('',#586);
#588=EDGE_CURVE('E876',#587,#579,#585,.T.);
#589=ORIENTED_EDGE('',*,*,#588,.F.);
#590=DIRECTION('',(0.,0.,1.));
#591=VECTOR('',#590,1.);
#592=CARTESIAN_POINT('',(6.07548935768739,3.81828327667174,1.27411800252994E-05));
#593=LINE('',#592,#591);
#594=EDGE_CURVE('E864',#557,#587,#593,.T.);
#595=ORIENTED_EDGE('',*,*,#594,.F.);
#596=ORIENTED_EDGE('',*,*,#558,.T.);
#597=EDGE_LOOP('',(#581,#589,#595,#596));
#598=FACE_BOUND('',#597,.T.);
#599=ADVANCED_FACE('F842',(#598),#573,.F.);
#600=CARTESIAN_POINT('',(4.08070933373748,3.82905308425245,1.11870748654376));
#601=DIRECTION('',(0.258815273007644,-0.0013973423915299,0.965925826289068));
#602=DIRECTION('',(0.965926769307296,0.,-0.258815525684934));
#603=AXIS2_PLACEMENT_3D('',#600,#601,#602);
#604=PLANE('',#603);
#605=ORIENTED_EDGE('',*,*,#517,.F.);
#606=ORIENTED_EDGE('',*,*,#410,.T.);
#607=DIRECTION('',(0.965911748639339,-0.0052149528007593,-0.258819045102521));
#608=VECTOR('',#607,1.);
#609=CARTESIAN_POINT('',(4.08070933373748,3.82905308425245,1.11870748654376));
#610=LINE('',#609,#608);
#611=EDGE_CURVE('E862',#402,#587,#610,.T.);
#612=ORIENTED_EDGE('',*,*,#611,.T.);
#613=ORIENTED_EDGE('',*,*,#588,.T.);
#614=DIRECTION('',(0.965911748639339,-0.0052149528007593,-0.258819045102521));
#615=VECTOR('',#614,1.);
#616=CARTESIAN_POINT('',(4.10127920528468,7.63899755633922,1.11870748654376));
#617=LINE('',#616,#615);
#618=EDGE_CURVE('E996',#516,#579,#617,.T.);
#619=ORIENTED_EDGE('',*,*,#618,.F.);
#620=EDGE_LOOP('',(#605,#606,#612,#613,#619));
#621=FACE_BOUND('',#620,.T.);
#622=ADVANCED_FACE('F837',(#621),#604,.T.);
#623=CARTESIAN_POINT('',(3.78096034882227,3.83067142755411,1.27411800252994E-05));
#624=DIRECTION('',(0.00539891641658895,0.999985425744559,0.));
#625=DIRECTION('',(-0.999985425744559,0.00539891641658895,0.));
#626=AXIS2_PLACEMENT_3D('',#623,#624,#625);
#627=PLANE('',#626);
#628=ORIENTED_EDGE('',*,*,#403,.F.);
#629=ORIENTED_EDGE('',*,*,#564,.T.);
#630=ORIENTED_EDGE('',*,*,#594,.T.);
#631=ORIENTED_EDGE('',*,*,#611,.F.);
#632=EDGE_LOOP('',(#628,#629,#630,#631));
#633=FACE_BOUND('',#632,.T.);
#634=ADVANCED_FACE('F833',(#633),#627,.F.);
#635=CARTESIAN_POINT('',(3.80153022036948,7.64061589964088,1.27411800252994E-05));
#636=DIRECTION('',(0.00539891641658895,0.999985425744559,0.));
#637=DIRECTION('',(-0.999985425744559,0.00539891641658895,0.));
#638=AXIS2_PLACEMENT_3D('',#635,#636,#637);
#639=PLANE('',#638);
#640=ORIENTED_EDGE('',*,*,#526,.F.);
#641=ORIENTED_EDGE('',*,*,#618,.T.);
#642=ORIENTED_EDGE('',*,*,#580,.F.);
#643=ORIENTED_EDGE('',*,*,#550,.F.);
#644=EDGE_LOOP('',(#640,#641,#642,#643));
#645=FACE_BOUND('',#644,.T.);
#646=ADVANCED_FACE('F827',(#645),#639,.T.);
#647=CARTESIAN_POINT('',(-0.0176216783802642,3.85119467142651,0.0101738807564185));
#648=DIRECTION('',(0.00467559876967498,0.999985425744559,-0.00269945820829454));
#649=DIRECTION('',(0.500000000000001,0.,0.866025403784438));
#650=AXIS2_PLACEMENT_3D('',#647,#648,#649);
#651=ELLIPSE('',#650,5.08,5.07992596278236);
#652=DIRECTION('',(0.00467559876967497,0.999985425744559,-0.00269945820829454));
#653=VECTOR('',#652,1.);
#654=SURFACE_OF_LINEAR_EXTRUSION('',#651,#653);
#655=ORIENTED_EDGE('',*,*,#434,.T.);
#656=DIRECTION('',(0.00467559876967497,0.999985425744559,-0.00269945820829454));
#657=VECTOR('',#656,1.);
#658=CARTESIAN_POINT('',(4.75405944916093,3.82418024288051,-1.73223813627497));
#659=LINE('',#658,#657);
#660=CARTESIAN_POINT('',(4.7718734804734,7.63412471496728,-1.74252307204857));
#661=VERTEX_POINT('',#660);
#662=EDGE_CURVE('E1016',#380,#661,#659,.T.);
#663=ORIENTED_EDGE('',*,*,#662,.T.);
#664=CARTESIAN_POINT('',(0.000192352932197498,7.66113914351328,-0.000111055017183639));
#665=DIRECTION('',(0.00467559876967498,0.999985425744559,-0.00269945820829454));
#666=DIRECTION('',(0.500000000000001,0.,0.866025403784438));
#667=AXIS2_PLACEMENT_3D('',#664,#665,#666);
#668=ELLIPSE('',#667,5.08,5.07992596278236);
#669=CARTESIAN_POINT('',(3.89500598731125,7.63412471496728,-3.26130212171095));
#670=VERTEX_POINT('',#669);
#671=EDGE_CURVE('E806',#661,#670,#668,.T.);
#672=ORIENTED_EDGE('',*,*,#671,.T.);
#673=DIRECTION('',(0.00467559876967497,0.999985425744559,-0.00269945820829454));
#674=VECTOR('',#673,1.);
#675=CARTESIAN_POINT('',(3.87719195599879,3.82418024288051,-3.25101718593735));
#676=LINE('',#675,#674);
#677=EDGE_CURVE('E1015',#353,#670,#676,.T.);
#678=ORIENTED_EDGE('',*,*,#677,.F.);
#679=EDGE_LOOP('',(#655,#663,#672,#678));
#680=FACE_BOUND('',#679,.T.);
#681=ADVANCED_FACE('F822',(#680),#654,.F.);
#682=CARTESIAN_POINT('',(2.97465057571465,3.82905304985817,-3.0091854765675));
#683=DIRECTION('',(0.25882231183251,0.0013973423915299,0.96592394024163));
#684=DIRECTION('',(0.965924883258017,0.,-0.258822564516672));
#685=AXIS2_PLACEMENT_3D('',#682,#683,#684);
#686=PLANE('',#685);
#687=ORIENTED_EDGE('',*,*,#363,.F.);
#688=ORIENTED_EDGE('',*,*,#677,.T.);
#689=DIRECTION('',(0.965913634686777,-0.0052149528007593,-0.258812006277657));
#690=VECTOR('',#689,1.);
#691=CARTESIAN_POINT('',(2.99246460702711,7.63899752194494,-3.0194704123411));
#692=LINE('',#691,#690);
#693=CARTESIAN_POINT('',(4.98724215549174,7.62822774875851,-3.55396165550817));
#694=VERTEX_POINT('',#693);
#695=EDGE_CURVE('E815',#670,#694,#692,.T.);
#696=ORIENTED_EDGE('',*,*,#695,.T.);
#697=DIRECTION('',(0.00467559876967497,0.999985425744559,-0.00269945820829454));
#698=VECTOR('',#697,1.);
#699=CARTESIAN_POINT('',(4.96942812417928,3.81828327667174,-3.54367671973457));
#700=LINE('',#699,#698);
#701=CARTESIAN_POINT('',(4.96942812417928,3.81828327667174,-3.54367671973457));
#702=VERTEX_POINT('',#701);
#703=EDGE_CURVE('E1021',#702,#694,#700,.T.);
#704=ORIENTED_EDGE('',*,*,#703,.F.);
#705=DIRECTION('',(0.965913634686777,-0.0052149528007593,-0.258812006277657));
#706=VECTOR('',#705,1.);
#707=CARTESIAN_POINT('',(2.97465057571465,3.82905304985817,-3.0091854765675));
#708=LINE('',#707,#706);
#709=EDGE_CURVE('E1019',#362,#702,#708,.T.);
#710=ORIENTED_EDGE('',*,*,#709,.F.);
#711=EDGE_LOOP('',(#687,#688,#696,#704,#710));
#712=FACE_BOUND('',#711,.T.);
#713=ADVANCED_FACE('F826',(#712),#686,.F.);
#714=CARTESIAN_POINT('',(5.26153449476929,3.81828327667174,-3.03773364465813));
#715=DIRECTION('',(-0.866012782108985,0.00539891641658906,0.49999271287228));
#716=DIRECTION('',(0.500000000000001,0.,0.866025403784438));
#717=AXIS2_PLACEMENT_3D('',#714,#715,#716);
#718=PLANE('',#717);
#719=DIRECTION('',(0.500000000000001,0.,0.866025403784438));
#720=VECTOR('',#719,1.);
#721=CARTESIAN_POINT('',(5.27934852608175,7.62822774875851,-3.04801858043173));
#722=LINE('',#721,#720);
#723=CARTESIAN_POINT('',(5.57144215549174,7.62822774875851,-2.54209757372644));
#724=VERTEX_POINT('',#723);
#725=EDGE_CURVE('E812',#694,#724,#722,.T.);
#726=ORIENTED_EDGE('',*,*,#725,.T.);
#727=DIRECTION('',(0.00467559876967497,0.999985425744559,-0.00269945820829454));
#728=VECTOR('',#727,1.);
#729=CARTESIAN_POINT('',(5.55362812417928,3.81828327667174,-2.53181263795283));
#730=LINE('',#729,#728);
#731=CARTESIAN_POINT('',(5.55362812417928,3.81828327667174,-2.53181263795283));
#732=VERTEX_POINT('',#731);
#733=EDGE_CURVE('E1018',#732,#724,#730,.T.);
#734=ORIENTED_EDGE('',*,*,#733,.F.);
#735=DIRECTION('',(0.500000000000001,0.,0.866025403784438));
#736=VECTOR('',#735,1.);
#737=CARTESIAN_POINT('',(5.26153449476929,3.81828327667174,-3.03773364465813));
#738=LINE('',#737,#736);
#739=EDGE_CURVE('E1025',#702,#732,#738,.T.);
#740=ORIENTED_EDGE('',*,*,#739,.F.);
#741=ORIENTED_EDGE('',*,*,#703,.T.);
#742=EDGE_LOOP('',(#726,#734,#740,#741));
#743=FACE_BOUND('',#742,.T.);
#744=ADVANCED_FACE('F1044',(#743),#718,.F.);
#745=CARTESIAN_POINT('',(4.09335169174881,3.82905308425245,-1.07152556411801));
#746=DIRECTION('',(0.70710351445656,-0.0013973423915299,0.707108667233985));
#747=DIRECTION('',(0.707109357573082,0.,-0.707104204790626));
#748=AXIS2_PLACEMENT_3D('',#745,#746,#747);
#749=PLANE('',#748);
#750=ORIENTED_EDGE('',*,*,#662,.F.);
#751=ORIENTED_EDGE('',*,*,#381,.T.);
#752=DIRECTION('',(0.707094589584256,-0.0052149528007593,-0.707099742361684));
#753=VECTOR('',#752,1.);
#754=CARTESIAN_POINT('',(4.09335169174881,3.82905308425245,-1.07152556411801));
#755=LINE('',#754,#753);
#756=EDGE_CURVE('E817',#371,#732,#755,.T.);
#757=ORIENTED_EDGE('',*,*,#756,.T.);
#758=ORIENTED_EDGE('',*,*,#733,.T.);
#759=DIRECTION('',(0.707094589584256,-0.0052149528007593,-0.707099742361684));
#760=VECTOR('',#759,1.);
#761=CARTESIAN_POINT('',(4.11116572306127,7.63899755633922,-1.08181049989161));
#762=LINE('',#761,#760);
#763=EDGE_CURVE('E809',#661,#724,#762,.T.);
#764=ORIENTED_EDGE('',*,*,#763,.F.);
#765=EDGE_LOOP('',(#750,#751,#757,#758,#764));
#766=FACE_BOUND('',#765,.T.);
#767=ADVANCED_FACE('F829',(#766),#749,.T.);
#768=CARTESIAN_POINT('',(3.27441408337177,3.83067142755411,-1.89046914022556));
#769=DIRECTION('',(0.00467559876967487,0.999985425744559,-0.00269945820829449));
#770=DIRECTION('',(-0.866012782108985,0.00539891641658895,0.499992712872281));
#771=AXIS2_PLACEMENT_3D('',#768,#769,#770);
#772=PLANE('',#771);
#773=ORIENTED_EDGE('',*,*,#372,.F.);
#774=ORIENTED_EDGE('',*,*,#709,.T.);
#775=ORIENTED_EDGE('',*,*,#739,.T.);
#776=ORIENTED_EDGE('',*,*,#756,.F.);
#777=EDGE_LOOP('',(#773,#774,#775,#776));
#778=FACE_BOUND('',#777,.T.);
#779=ADVANCED_FACE('F1035',(#778),#772,.F.);
#780=CARTESIAN_POINT('',(3.29222811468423,7.64061589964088,-1.90075407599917));
#781=DIRECTION('',(0.00467559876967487,0.999985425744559,-0.00269945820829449));
#782=DIRECTION('',(-0.866012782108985,0.00539891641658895,0.499992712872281));
#783=AXIS2_PLACEMENT_3D('',#780,#781,#782);
#784=PLANE('',#783);
#785=ORIENTED_EDGE('',*,*,#671,.F.);
#786=ORIENTED_EDGE('',*,*,#763,.T.);
#787=ORIENTED_EDGE('',*,*,#725,.F.);
#788=ORIENTED_EDGE('',*,*,#695,.F.);
#789=EDGE_LOOP('',(#785,#786,#787,#788));
#790=FACE_BOUND('',#789,.T.);
#791=ADVANCED_FACE('F777',(#790),#784,.T.);
#792=CARTESIAN_POINT('',(-0.0101738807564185,3.85119467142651,0.0176216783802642));
#793=DIRECTION('',(0.00269945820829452,0.999985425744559,-0.00467559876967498));
#794=DIRECTION('',(0.86602540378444,0.,0.499999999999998));
#795=AXIS2_PLACEMENT_3D('',#792,#793,#794);
#796=ELLIPSE('',#795,5.08,5.07992596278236);
#797=DIRECTION('',(0.00269945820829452,0.999985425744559,-0.00467559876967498));
#798=VECTOR('',#797,1.);
#799=SURFACE_OF_LINEAR_EXTRUSION('',#796,#798);
#800=ORIENTED_EDGE('',*,*,#437,.T.);
#801=DIRECTION('',(0.00269945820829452,0.999985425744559,-0.00467559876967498));
#802=VECTOR('',#801,1.);
#803=CARTESIAN_POINT('',(3.25101718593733,3.82418024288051,-3.87719195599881));
#804=LINE('',#803,#802);
#805=CARTESIAN_POINT('',(3.26130212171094,7.63412471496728,-3.89500598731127));
#806=VERTEX_POINT('',#805);
#807=EDGE_CURVE('E792',#349,#806,#804,.T.);
#808=ORIENTED_EDGE('',*,*,#807,.T.);
#809=CARTESIAN_POINT('',(0.000111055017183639,7.66113914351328,-0.000192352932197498));
#810=DIRECTION('',(0.00269945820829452,0.999985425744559,-0.00467559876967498));
#811=DIRECTION('',(0.86602540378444,0.,0.499999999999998));
#812=AXIS2_PLACEMENT_3D('',#809,#810,#811);
#813=ELLIPSE('',#812,5.08,5.07992596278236);
#814=CARTESIAN_POINT('',(1.74252307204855,7.63412471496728,-4.7718734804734));
#815=VERTEX_POINT('',#814);
#816=EDGE_CURVE('E1105',#806,#815,#813,.T.);
#817=ORIENTED_EDGE('',*,*,#816,.T.);
#818=DIRECTION('',(0.00269945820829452,0.999985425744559,-0.00467559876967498));
#819=VECTOR('',#818,1.);
#820=CARTESIAN_POINT('',(1.73223813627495,3.82418024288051,-4.75405944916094));
#821=LINE('',#820,#819);
#822=EDGE_CURVE('E793',#322,#815,#821,.T.);
#823=ORIENTED_EDGE('',*,*,#822,.F.);
#824=EDGE_LOOP('',(#800,#808,#817,#823));
#825=FACE_BOUND('',#824,.T.);
#826=ADVANCED_FACE('F766',(#825),#799,.F.);
#827=CARTESIAN_POINT('',(1.07153022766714,3.82905304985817,-4.09335635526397));
#828=DIRECTION('',(0.707108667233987,0.0013973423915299,0.707103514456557));
#829=DIRECTION('',(0.707104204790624,0.,-0.707109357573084));
#830=AXIS2_PLACEMENT_3D('',#827,#828,#829);
#831=PLANE('',#830);
#832=ORIENTED_EDGE('',*,*,#332,.F.);
#833=ORIENTED_EDGE('',*,*,#822,.T.);
#834=DIRECTION('',(0.707099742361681,-0.0052149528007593,-0.707094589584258));
#835=VECTOR('',#834,1.);
#836=CARTESIAN_POINT('',(1.08181516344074,7.63899752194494,-4.11117038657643));
#837=LINE('',#836,#835);
#838=CARTESIAN_POINT('',(2.54209757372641,7.62822774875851,-5.57144215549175));
#839=VERTEX_POINT('',#838);
#840=EDGE_CURVE('E783',#815,#839,#837,.T.);
#841=ORIENTED_EDGE('',*,*,#840,.T.);
#842=DIRECTION('',(0.00269945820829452,0.999985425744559,-0.00467559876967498));
#843=VECTOR('',#842,1.);
#844=CARTESIAN_POINT('',(2.53181263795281,3.81828327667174,-5.55362812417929));
#845=LINE('',#844,#843);
#846=CARTESIAN_POINT('',(2.53181263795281,3.81828327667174,-5.55362812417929));
#847=VERTEX_POINT('',#846);
#848=EDGE_CURVE('E796',#847,#839,#845,.T.);
#849=ORIENTED_EDGE('',*,*,#848,.F.);
#850=DIRECTION('',(0.707099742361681,-0.0052149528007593,-0.707094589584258));
#851=VECTOR('',#850,1.);
#852=CARTESIAN_POINT('',(1.07153022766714,3.82905304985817,-4.09335635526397));
#853=LINE('',#852,#851);
#854=EDGE_CURVE('E790',#331,#847,#853,.T.);
#855=ORIENTED_EDGE('',*,*,#854,.F.);
#856=EDGE_LOOP('',(#832,#833,#841,#849,#855));
#857=FACE_BOUND('',#856,.T.);
#858=ADVANCED_FACE('F762',(#857),#831,.F.);
#859=CARTESIAN_POINT('',(3.03775571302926,3.81828327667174,-5.26152175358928));
#860=DIRECTION('',(-0.499992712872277,0.00539891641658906,0.866012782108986));
#861=DIRECTION('',(0.86602540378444,0.,0.499999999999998));
#862=AXIS2_PLACEMENT_3D('',#859,#860,#861);
#863=PLANE('',#862);
#864=DIRECTION('',(0.86602540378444,0.,0.499999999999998));
#865=VECTOR('',#864,1.);
#866=CARTESIAN_POINT('',(3.04804064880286,7.62822774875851,-5.27933578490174));
#867=LINE('',#866,#865);
#868=CARTESIAN_POINT('',(3.55396165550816,7.62822774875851,-4.98724215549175));
#869=VERTEX_POINT('',#868);
#870=EDGE_CURVE('E1104',#839,#869,#867,.T.);
#871=ORIENTED_EDGE('',*,*,#870,.T.);
#872=DIRECTION('',(0.00269945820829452,0.999985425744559,-0.00467559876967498));
#873=VECTOR('',#872,1.);
#874=CARTESIAN_POINT('',(3.54367671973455,3.81828327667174,-4.96942812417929));
#875=LINE('',#874,#873);
#876=CARTESIAN_POINT('',(3.54367671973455,3.81828327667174,-4.96942812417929));
#877=VERTEX_POINT('',#876);
#878=EDGE_CURVE('E799',#877,#869,#875,.T.);
#879=ORIENTED_EDGE('',*,*,#878,.F.);
#880=DIRECTION('',(0.86602540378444,0.,0.499999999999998));
#881=VECTOR('',#880,1.);
#882=CARTESIAN_POINT('',(3.03775571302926,3.81828327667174,-5.26152175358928));
#883=LINE('',#882,#881);
#884=EDGE_CURVE('E787',#847,#877,#883,.T.);
#885=ORIENTED_EDGE('',*,*,#884,.F.);
#886=ORIENTED_EDGE('',*,*,#848,.T.);
#887=EDGE_LOOP('',(#871,#879,#885,#886));
#888=FACE_BOUND('',#887,.T.);
#889=ADVANCED_FACE('F765',(#888),#863,.F.);
#890=CARTESIAN_POINT('',(3.00918376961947,3.82905308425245,-2.97464420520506));
#891=DIRECTION('',(0.965923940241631,-0.0013973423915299,0.258822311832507));
#892=DIRECTION('',(0.258822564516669,0.,-0.965924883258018));
#893=AXIS2_PLACEMENT_3D('',#890,#891,#892);
#894=PLANE('',#893);
#895=ORIENTED_EDGE('',*,*,#807,.F.);
#896=ORIENTED_EDGE('',*,*,#350,.T.);
#897=DIRECTION('',(0.258812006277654,-0.0052149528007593,-0.965913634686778));
#898=VECTOR('',#897,1.);
#899=CARTESIAN_POINT('',(3.00918376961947,3.82905308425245,-2.97464420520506));
#900=LINE('',#899,#898);
#901=EDGE_CURVE('E785',#340,#877,#900,.T.);
#902=ORIENTED_EDGE('',*,*,#901,.T.);
#903=ORIENTED_EDGE('',*,*,#878,.T.);
#904=DIRECTION('',(0.258812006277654,-0.0052149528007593,-0.965913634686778));
#905=VECTOR('',#904,1.);
#906=CARTESIAN_POINT('',(3.01946870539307,7.63899755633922,-2.99245823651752));
#907=LINE('',#906,#905);
#908=EDGE_CURVE('E1100',#806,#869,#907,.T.);
#909=ORIENTED_EDGE('',*,*,#908,.F.);
#910=EDGE_LOOP('',(#895,#896,#902,#903,#909));
#911=FACE_BOUND('',#910,.T.);
#912=ADVANCED_FACE('F760',(#911),#894,.T.);
#913=CARTESIAN_POINT('',(1.8904912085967,3.83067142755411,-3.27440134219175));
#914=DIRECTION('',(0.00269945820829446,0.999985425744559,-0.00467559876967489));
#915=DIRECTION('',(-0.499992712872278,0.00539891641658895,0.866012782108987));
#916=AXIS2_PLACEMENT_3D('',#913,#914,#915);
#917=PLANE('',#916);
#918=ORIENTED_EDGE('',*,*,#341,.F.);
#919=ORIENTED_EDGE('',*,*,#854,.T.);
#920=ORIENTED_EDGE('',*,*,#884,.T.);
#921=ORIENTED_EDGE('',*,*,#901,.F.);
#922=EDGE_LOOP('',(#918,#919,#920,#921));
#923=FACE_BOUND('',#922,.T.);
#924=ADVANCED_FACE('F756',(#923),#917,.F.);
#925=CARTESIAN_POINT('',(1.90077614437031,7.64061589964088,-3.29221537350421));
#926=DIRECTION('',(0.00269945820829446,0.999985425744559,-0.00467559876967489));
#927=DIRECTION('',(-0.499992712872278,0.00539891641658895,0.866012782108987));
#928=AXIS2_PLACEMENT_3D('',#925,#926,#927);
#929=PLANE('',#928);
#930=ORIENTED_EDGE('',*,*,#816,.F.);
#931=ORIENTED_EDGE('',*,*,#908,.T.);
#932=ORIENTED_EDGE('',*,*,#870,.F.);
#933=ORIENTED_EDGE('',*,*,#840,.F.);
#934=EDGE_LOOP('',(#930,#931,#932,#933));
#935=FACE_BOUND('',#934,.T.);
#936=ADVANCED_FACE('F750',(#935),#929,.T.);
#937=CARTESIAN_POINT('',(0.,3.85119467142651,0.0203477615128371));
#938=DIRECTION('',(0.,0.999985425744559,-0.00539891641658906));
#939=DIRECTION('',(1.,0.,0.));
#940=AXIS2_PLACEMENT_3D('',#937,#938,#939);
#941=ELLIPSE('',#940,5.08,5.07992596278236);
#942=DIRECTION('',(0.,0.999985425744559,-0.00539891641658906));
#943=VECTOR('',#942,1.);
#944=SURFACE_OF_LINEAR_EXTRUSION('',#941,#943);
#945=ORIENTED_EDGE('',*,*,#440,.T.);
#946=DIRECTION('',(0.,0.999985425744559,-0.00539891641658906));
#947=VECTOR('',#946,1.);
#948=CARTESIAN_POINT('',(0.876867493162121,3.82418024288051,-4.98325532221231));
#949=LINE('',#948,#947);
#950=CARTESIAN_POINT('',(0.876867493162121,7.63412471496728,-5.00382519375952));
#951=VERTEX_POINT('',#950);
#952=EDGE_CURVE('E1115',#318,#951,#949,.T.);
#953=ORIENTED_EDGE('',*,*,#952,.T.);
#954=CARTESIAN_POINT('',(0.,7.66113914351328,-0.000222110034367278));
#955=DIRECTION('',(0.,0.999985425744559,-0.00539891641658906));
#956=DIRECTION('',(1.,0.,0.));
#957=AXIS2_PLACEMENT_3D('',#954,#955,#956);
#958=ELLIPSE('',#957,5.08,5.07992596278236);
#959=CARTESIAN_POINT('',(-0.876867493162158,7.63412471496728,-5.00382519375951));
#960=VERTEX_POINT('',#959);
#961=EDGE_CURVE('E729',#951,#960,#958,.T.);
#962=ORIENTED_EDGE('',*,*,#961,.T.);
#963=DIRECTION('',(0.,0.999985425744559,-0.00539891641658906));
#964=VECTOR('',#963,1.);
#965=CARTESIAN_POINT('',(-0.876867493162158,3.82418024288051,-4.9832553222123));
#966=LINE('',#965,#964);
#967=EDGE_CURVE('E1114',#291,#960,#966,.T.);
#968=ORIENTED_EDGE('',*,*,#967,.F.);
#969=EDGE_LOOP('',(#945,#953,#962,#968));
#970=FACE_BOUND('',#969,.T.);
#971=ADVANCED_FACE('F745',(#970),#944,.F.);
#972=CARTESIAN_POINT('',(-1.11870577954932,3.82905304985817,-4.08071570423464));
#973=DIRECTION('',(0.965925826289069,0.0013973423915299,0.258815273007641));
#974=DIRECTION('',(0.258815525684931,0.,-0.965926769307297));
#975=AXIS2_PLACEMENT_3D('',#972,#973,#974);
#976=PLANE('',#975);
#977=ORIENTED_EDGE('',*,*,#301,.F.);
#978=ORIENTED_EDGE('',*,*,#967,.T.);
#979=DIRECTION('',(0.258819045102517,-0.0052149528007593,-0.96591174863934));
#980=VECTOR('',#979,1.);
#981=CARTESIAN_POINT('',(-1.11870577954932,7.63899752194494,-4.10128557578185));
#982=LINE('',#981,#980);
#983=CARTESIAN_POINT('',(-0.584200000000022,7.62822774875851,-6.09605922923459));
#984=VERTEX_POINT('',#983);
#985=EDGE_CURVE('E738',#960,#984,#982,.T.);
#986=ORIENTED_EDGE('',*,*,#985,.T.);
#987=DIRECTION('',(0.,0.999985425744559,-0.00539891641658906));
#988=VECTOR('',#987,1.);
#989=CARTESIAN_POINT('',(-0.584200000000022,3.81828327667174,-6.07548935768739));
#990=LINE('',#989,#988);
#991=CARTESIAN_POINT('',(-0.584200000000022,3.81828327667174,-6.07548935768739));
#992=VERTEX_POINT('',#991);
#993=EDGE_CURVE('E1120',#992,#984,#990,.T.);
#994=ORIENTED_EDGE('',*,*,#993,.F.);
#995=DIRECTION('',(0.258819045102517,-0.0052149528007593,-0.96591174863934));
#996=VECTOR('',#995,1.);
#997=CARTESIAN_POINT('',(-1.11870577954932,3.82905304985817,-4.08071570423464));
#998=LINE('',#997,#996);
#999=EDGE_CURVE('E1118',#300,#992,#998,.T.);
#1000=ORIENTED_EDGE('',*,*,#999,.F.);
#1001=EDGE_LOOP('',(#977,#978,#986,#994,#1000));
#1002=FACE_BOUND('',#1001,.T.);
#1003=ADVANCED_FACE('F749',(#1002),#976,.F.);
#1004=CARTESIAN_POINT('',(1.27411800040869E-05,3.81828327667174,-6.07548935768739));
#1005=DIRECTION('',(0.,0.00539891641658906,0.999985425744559));
#1006=DIRECTION('',(0.,-0.999985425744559,0.00539891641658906));
#1007=AXIS2_PLACEMENT_3D('',#1004,#1005,#1006);
#1008=PLANE('',#1007);
#1009=DIRECTION('',(1.,0.,0.));
#1010=VECTOR('',#1009,1.);
#1011=CARTESIAN_POINT('',(1.27411800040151E-05,7.62822774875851,-6.0960592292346));
#1012=LINE('',#1011,#1010);
#1013=CARTESIAN_POINT('',(0.584199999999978,7.62822774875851,-6.0960592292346));
#1014=VERTEX_POINT('',#1013);
#1015=EDGE_CURVE('E735',#984,#1014,#1012,.T.);
#1016=ORIENTED_EDGE('',*,*,#1015,.T.);
#1017=DIRECTION('',(0.,0.999985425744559,-0.00539891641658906));
#1018=VECTOR('',#1017,1.);
#1019=CARTESIAN_POINT('',(0.584199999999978,3.81828327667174,-6.07548935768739));
#1020=LINE('',#1019,#1018);
#1021=CARTESIAN_POINT('',(0.584199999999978,3.81828327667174,-6.07548935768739));
#1022=VERTEX_POINT('',#1021);
#1023=EDGE_CURVE('E1117',#1022,#1014,#1020,.T.);
#1024=ORIENTED_EDGE('',*,*,#1023,.F.);
#1025=DIRECTION('',(1.,0.,0.));
#1026=VECTOR('',#1025,1.);
#1027=CARTESIAN_POINT('',(1.27411800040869E-05,3.81828327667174,-6.07548935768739));
#1028=LINE('',#1027,#1026);
#1029=EDGE_CURVE('E1124',#992,#1022,#1028,.T.);
#1030=ORIENTED_EDGE('',*,*,#1029,.F.);
#1031=ORIENTED_EDGE('',*,*,#993,.T.);
#1032=EDGE_LOOP('',(#1016,#1024,#1030,#1031));
#1033=FACE_BOUND('',#1032,.T.);
#1034=ADVANCED_FACE('F1142',(#1033),#1008,.F.);
#1035=CARTESIAN_POINT('',(1.11870748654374,3.82905308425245,-4.08070933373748));
#1036=DIRECTION('',(0.965925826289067,-0.0013973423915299,-0.258815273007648));
#1037=DIRECTION('',(-0.258815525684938,0.,-0.965926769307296));
#1038=AXIS2_PLACEMENT_3D('',#1035,#1036,#1037);
#1039=PLANE('',#1038);
#1040=ORIENTED_EDGE('',*,*,#952,.F.);
#1041=ORIENTED_EDGE('',*,*,#319,.T.);
#1042=DIRECTION('',(-0.258819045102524,-0.0052149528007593,-0.965911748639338));
#1043=VECTOR('',#1042,1.);
#1044=CARTESIAN_POINT('',(1.11870748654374,3.82905308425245,-4.08070933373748));
#1045=LINE('',#1044,#1043);
#1046=EDGE_CURVE('E740',#309,#1022,#1045,.T.);
#1047=ORIENTED_EDGE('',*,*,#1046,.T.);
#1048=ORIENTED_EDGE('',*,*,#1023,.T.);
#1049=DIRECTION('',(-0.258819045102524,-0.0052149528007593,-0.965911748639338));
#1050=VECTOR('',#1049,1.);
#1051=CARTESIAN_POINT('',(1.11870748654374,7.63899755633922,-4.10127920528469));
#1052=LINE('',#1051,#1050);
#1053=EDGE_CURVE('E732',#951,#1014,#1052,.T.);
#1054=ORIENTED_EDGE('',*,*,#1053,.F.);
#1055=EDGE_LOOP('',(#1040,#1041,#1047,#1048,#1054));
#1056=FACE_BOUND('',#1055,.T.);
#1057=ADVANCED_FACE('F752',(#1056),#1039,.T.);
#1058=CARTESIAN_POINT('',(1.27411800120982E-05,3.83067142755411,-3.78096034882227));
#1059=DIRECTION('',(0.,0.999985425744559,-0.00539891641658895));
#1060=DIRECTION('',(0.,0.00539891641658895,0.999985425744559));
#1061=AXIS2_PLACEMENT_3D('',#1058,#1059,#1060);
#1062=PLANE('',#1061);
#1063=ORIENTED_EDGE('',*,*,#310,.F.);
#1064=ORIENTED_EDGE('',*,*,#999,.T.);
#1065=ORIENTED_EDGE('',*,*,#1029,.T.);
#1066=ORIENTED_EDGE('',*,*,#1046,.F.);
#1067=EDGE_LOOP('',(#1063,#1064,#1065,#1066));
#1068=FACE_BOUND('',#1067,.T.);
#1069=ADVANCED_FACE('F1134',(#1068),#1062,.F.);
#1070=CARTESIAN_POINT('',(1.27411800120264E-05,7.64061589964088,-3.80153022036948));
#1071=DIRECTION('',(0.,0.999985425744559,-0.00539891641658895));
#1072=DIRECTION('',(0.,0.00539891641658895,0.999985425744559));
#1073=AXIS2_PLACEMENT_3D('',#1070,#1071,#1072);
#1074=PLANE('',#1073);
#1075=ORIENTED_EDGE('',*,*,#961,.F.);
#1076=ORIENTED_EDGE('',*,*,#1053,.T.);
#1077=ORIENTED_EDGE('',*,*,#1015,.F.);
#1078=ORIENTED_EDGE('',*,*,#985,.F.);
#1079=EDGE_LOOP('',(#1075,#1076,#1077,#1078));
#1080=FACE_BOUND('',#1079,.T.);
#1081=ADVANCED_FACE('F700',(#1080),#1074,.T.);
#1082=CARTESIAN_POINT('',(0.0101738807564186,3.85119467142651,0.0176216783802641));
#1083=DIRECTION('',(-0.00269945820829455,0.999985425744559,-0.00467559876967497));
#1084=DIRECTION('',(0.866025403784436,0.,-0.500000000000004));
#1085=AXIS2_PLACEMENT_3D('',#1082,#1083,#1084);
#1086=ELLIPSE('',#1085,5.08,5.07992596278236);
#1087=DIRECTION('',(-0.00269945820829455,0.999985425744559,-0.00467559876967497));
#1088=VECTOR('',#1087,1.);
#1089=SURFACE_OF_LINEAR_EXTRUSION('',#1086,#1088);
#1090=ORIENTED_EDGE('',*,*,#443,.T.);
#1091=DIRECTION('',(-0.00269945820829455,0.999985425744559,-0.00467559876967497));
#1092=VECTOR('',#1091,1.);
#1093=CARTESIAN_POINT('',(-1.73223813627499,3.82418024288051,-4.75405944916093));
#1094=LINE('',#1093,#1092);
#1095=CARTESIAN_POINT('',(-1.74252307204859,7.63412471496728,-4.77187348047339));
#1096=VERTEX_POINT('',#1095);
#1097=EDGE_CURVE('E715',#287,#1096,#1094,.T.);
#1098=ORIENTED_EDGE('',*,*,#1097,.T.);
#1099=CARTESIAN_POINT('',(-0.00011105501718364,7.66113914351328,-0.000192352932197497));
#1100=DIRECTION('',(-0.00269945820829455,0.999985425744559,-0.00467559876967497));
#1101=DIRECTION('',(0.866025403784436,0.,-0.500000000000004));
#1102=AXIS2_PLACEMENT_3D('',#1099,#1100,#1101);
#1103=ELLIPSE('',#1102,5.08,5.07992596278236);
#1104=CARTESIAN_POINT('',(-3.26130212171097,7.63412471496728,-3.89500598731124));
#1105=VERTEX_POINT('',#1104);
#1106=EDGE_CURVE('E1637',#1096,#1105,#1103,.T.);
#1107=ORIENTED_EDGE('',*,*,#1106,.T.);
#1108=DIRECTION('',(-0.00269945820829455,0.999985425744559,-0.00467559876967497));
#1109=VECTOR('',#1108,1.);
#1110=CARTESIAN_POINT('',(-3.25101718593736,3.82418024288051,-3.87719195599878));
#1111=LINE('',#1110,#1109);
#1112=EDGE_CURVE('E716',#260,#1105,#1111,.T.);
#1113=ORIENTED_EDGE('',*,*,#1112,.F.);
#1114=EDGE_LOOP('',(#1090,#1098,#1107,#1113));
#1115=FACE_BOUND('',#1114,.T.);
#1116=ADVANCED_FACE('F689',(#1115),#1089,.F.);
#1117=CARTESIAN_POINT('',(-3.00918547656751,3.82905304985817,-2.97465057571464));
#1118=DIRECTION('',(0.965923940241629,0.0013973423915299,-0.258822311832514));
#1119=DIRECTION('',(-0.258822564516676,0.,-0.965924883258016));
#1120=AXIS2_PLACEMENT_3D('',#1117,#1118,#1119);
#1121=PLANE('',#1120);
#1122=ORIENTED_EDGE('',*,*,#270,.F.);
#1123=ORIENTED_EDGE('',*,*,#1112,.T.);
#1124=DIRECTION('',(-0.258812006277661,-0.0052149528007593,-0.965913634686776));
#1125=VECTOR('',#1124,1.);
#1126=CARTESIAN_POINT('',(-3.01947041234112,7.63899752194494,-2.9924646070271));
#1127=LINE('',#1126,#1125);
#1128=CARTESIAN_POINT('',(-3.55396165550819,7.62822774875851,-4.98724215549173));
#1129=VERTEX_POINT('',#1128);
#1130=EDGE_CURVE('E706',#1105,#1129,#1127,.T.);
#1131=ORIENTED_EDGE('',*,*,#1130,.T.);
#1132=DIRECTION('',(-0.00269945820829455,0.999985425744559,-0.00467559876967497));
#1133=VECTOR('',#1132,1.);
#1134=CARTESIAN_POINT('',(-3.54367671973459,3.81828327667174,-4.96942812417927));
#1135=LINE('',#1134,#1133);
#1136=CARTESIAN_POINT('',(-3.54367671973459,3.81828327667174,-4.96942812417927));
#1137=VERTEX_POINT('',#1136);
#1138=EDGE_CURVE('E719',#1137,#1129,#1135,.T.);
#1139=ORIENTED_EDGE('',*,*,#1138,.F.);
#1140=DIRECTION('',(-0.258812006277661,-0.0052149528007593,-0.965913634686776));
#1141=VECTOR('',#1140,1.);
#1142=CARTESIAN_POINT('',(-3.00918547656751,3.82905304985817,-2.97465057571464));
#1143=LINE('',#1142,#1141);
#1144=EDGE_CURVE('E713',#269,#1137,#1143,.T.);
#1145=ORIENTED_EDGE('',*,*,#1144,.F.);
#1146=EDGE_LOOP('',(#1122,#1123,#1131,#1139,#1145));
#1147=FACE_BOUND('',#1146,.T.);
#1148=ADVANCED_FACE('F685',(#1147),#1121,.F.);
#1149=CARTESIAN_POINT('',(-3.03773364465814,3.81828327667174,-5.26153449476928));
#1150=DIRECTION('',(0.499992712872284,0.00539891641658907,0.866012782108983));
#1151=DIRECTION('',(0.866025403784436,0.,-0.500000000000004));
#1152=AXIS2_PLACEMENT_3D('',#1149,#1150,#1151);
#1153=PLANE('',#1152);
#1154=DIRECTION('',(0.866025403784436,0.,-0.500000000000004));
#1155=VECTOR('',#1154,1.);
#1156=CARTESIAN_POINT('',(-3.04801858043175,7.62822774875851,-5.27934852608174));
#1157=LINE('',#1156,#1155);
#1158=CARTESIAN_POINT('',(-2.54209757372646,7.62822774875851,-5.57144215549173));
#1159=VERTEX_POINT('',#1158);
#1160=EDGE_CURVE('E1657',#1129,#1159,#1157,.T.);
#1161=ORIENTED_EDGE('',*,*,#1160,.T.);
#1162=DIRECTION('',(-0.00269945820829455,0.999985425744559,-0.00467559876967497));
#1163=VECTOR('',#1162,1.);
#1164=CARTESIAN_POINT('',(-2.53181263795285,3.81828327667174,-5.55362812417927));
#1165=LINE('',#1164,#1163);
#1166=CARTESIAN_POINT('',(-2.53181263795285,3.81828327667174,-5.55362812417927));
#1167=VERTEX_POINT('',#1166);
#1168=EDGE_CURVE('E722',#1167,#1159,#1165,.T.);
#1169=ORIENTED_EDGE('',*,*,#1168,.F.);
#1170=DIRECTION('',(0.866025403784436,0.,-0.500000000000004));
#1171=VECTOR('',#1170,1.);
#1172=CARTESIAN_POINT('',(-3.03773364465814,3.81828327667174,-5.26153449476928));
#1173=LINE('',#1172,#1171);
#1174=EDGE_CURVE('E710',#1137,#1167,#1173,.T.);
#1175=ORIENTED_EDGE('',*,*,#1174,.F.);
#1176=ORIENTED_EDGE('',*,*,#1138,.T.);
#1177=EDGE_LOOP('',(#1161,#1169,#1175,#1176));
#1178=FACE_BOUND('',#1177,.T.);
#1179=ADVANCED_FACE('F688',(#1178),#1153,.F.);
#1180=CARTESIAN_POINT('',(-1.07152556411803,3.82905308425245,-4.0933516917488));
#1181=DIRECTION('',(0.707108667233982,-0.00139734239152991,-0.707103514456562));
#1182=DIRECTION('',(-0.707104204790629,0.,-0.707109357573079));
#1183=AXIS2_PLACEMENT_3D('',#1180,#1181,#1182);
#1184=PLANE('',#1183);
#1185=ORIENTED_EDGE('',*,*,#1097,.F.);
#1186=ORIENTED_EDGE('',*,*,#288,.T.);
#1187=DIRECTION('',(-0.707099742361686,-0.0052149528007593,-0.707094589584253));
#1188=VECTOR('',#1187,1.);
#1189=CARTESIAN_POINT('',(-1.07152556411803,3.82905308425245,-4.0933516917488));
#1190=LINE('',#1189,#1188);
#1191=EDGE_CURVE('E708',#278,#1167,#1190,.T.);
#1192=ORIENTED_EDGE('',*,*,#1191,.T.);
#1193=ORIENTED_EDGE('',*,*,#1168,.T.);
#1194=DIRECTION('',(-0.707099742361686,-0.0052149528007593,-0.707094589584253));
#1195=VECTOR('',#1194,1.);
#1196=CARTESIAN_POINT('',(-1.08181049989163,7.63899755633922,-4.11116572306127));
#1197=LINE('',#1196,#1195);
#1198=EDGE_CURVE('E1655',#1096,#1159,#1197,.T.);
#1199=ORIENTED_EDGE('',*,*,#1198,.F.);
#1200=EDGE_LOOP('',(#1185,#1186,#1192,#1193,#1199));
#1201=FACE_BOUND('',#1200,.T.);
#1202=ADVANCED_FACE('F683',(#1201),#1184,.T.);
#1203=CARTESIAN_POINT('',(-1.89046914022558,3.83067142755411,-3.27441408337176));
#1204=DIRECTION('',(-0.00269945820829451,0.999985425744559,-0.00467559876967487));
#1205=DIRECTION('',(0.499992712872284,0.00539891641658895,0.866012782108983));
#1206=AXIS2_PLACEMENT_3D('',#1203,#1204,#1205);
#1207=PLANE('',#1206);
#1208=ORIENTED_EDGE('',*,*,#279,.F.);
#1209=ORIENTED_EDGE('',*,*,#1144,.T.);
#1210=ORIENTED_EDGE('',*,*,#1174,.T.);
#1211=ORIENTED_EDGE('',*,*,#1191,.F.);
#1212=EDGE_LOOP('',(#1208,#1209,#1210,#1211));
#1213=FACE_BOUND('',#1212,.T.);
#1214=ADVANCED_FACE('F679',(#1213),#1207,.F.);
#1215=CARTESIAN_POINT('',(-1.90075407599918,7.64061589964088,-3.29222811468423));
#1216=DIRECTION('',(-0.00269945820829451,0.999985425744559,-0.00467559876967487));
#1217=DIRECTION('',(0.499992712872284,0.00539891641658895,0.866012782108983));
#1218=AXIS2_PLACEMENT_3D('',#1215,#1216,#1217);
#1219=PLANE('',#1218);
#1220=ORIENTED_EDGE('',*,*,#1106,.F.);
#1221=ORIENTED_EDGE('',*,*,#1198,.T.);
#1222=ORIENTED_EDGE('',*,*,#1160,.F.);
#1223=ORIENTED_EDGE('',*,*,#1130,.F.);
#1224=EDGE_LOOP('',(#1220,#1221,#1222,#1223));
#1225=FACE_BOUND('',#1224,.T.);
#1226=ADVANCED_FACE('F673',(#1225),#1219,.T.);
#1227=CARTESIAN_POINT('',(0.0176216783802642,3.85119467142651,0.0101738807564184));
#1228=DIRECTION('',(-0.00467559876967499,0.999985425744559,-0.0026994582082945));
#1229=DIRECTION('',(0.499999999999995,0.,-0.866025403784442));
#1230=AXIS2_PLACEMENT_3D('',#1227,#1228,#1229);
#1231=ELLIPSE('',#1230,5.08,5.07992596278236);
#1232=DIRECTION('',(-0.00467559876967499,0.999985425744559,-0.0026994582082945));
#1233=VECTOR('',#1232,1.);
#1234=SURFACE_OF_LINEAR_EXTRUSION('',#1231,#1233);
#1235=ORIENTED_EDGE('',*,*,#446,.T.);
#1236=DIRECTION('',(-0.00467559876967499,0.999985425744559,-0.0026994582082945));
#1237=VECTOR('',#1236,1.);
#1238=CARTESIAN_POINT('',(-3.87719195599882,3.82418024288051,-3.25101718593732));
#1239=LINE('',#1238,#1237);
#1240=CARTESIAN_POINT('',(-3.89500598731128,7.63412471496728,-3.26130212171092));
#1241=VERTEX_POINT('',#1240);
#1242=EDGE_CURVE('E1651',#256,#1241,#1239,.T.);
#1243=ORIENTED_EDGE('',*,*,#1242,.T.);
#1244=CARTESIAN_POINT('',(-0.000192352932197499,7.66113914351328,-0.000111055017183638));
#1245=DIRECTION('',(-0.00467559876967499,0.999985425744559,-0.0026994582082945));
#1246=DIRECTION('',(0.499999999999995,0.,-0.866025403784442));
#1247=AXIS2_PLACEMENT_3D('',#1244,#1245,#1246);
#1248=ELLIPSE('',#1247,5.08,5.07992596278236);
#1249=CARTESIAN_POINT('',(-4.77187348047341,7.63412471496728,-1.74252307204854));
#1250=VERTEX_POINT('',#1249);
#1251=EDGE_CURVE('E652',#1241,#1250,#1248,.T.);
#1252=ORIENTED_EDGE('',*,*,#1251,.T.);
#1253=DIRECTION('',(-0.00467559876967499,0.999985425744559,-0.0026994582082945));
#1254=VECTOR('',#1253,1.);
#1255=CARTESIAN_POINT('',(-4.75405944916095,3.82418024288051,-1.73223813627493));
#1256=LINE('',#1255,#1254);
#1257=EDGE_CURVE('E1632',#229,#1250,#1256,.T.);
#1258=ORIENTED_EDGE('',*,*,#1257,.F.);
#1259=EDGE_LOOP('',(#1235,#1243,#1252,#1258));
#1260=FACE_BOUND('',#1259,.T.);
#1261=ADVANCED_FACE('F668',(#1260),#1234,.F.);
#1262=CARTESIAN_POINT('',(-4.09335635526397,3.82905304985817,-1.07153022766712));
#1263=DIRECTION('',(0.707103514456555,0.0013973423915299,-0.70710866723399));
#1264=DIRECTION('',(-0.707109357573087,0.,-0.707104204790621));
#1265=AXIS2_PLACEMENT_3D('',#1262,#1263,#1264);
#1266=PLANE('',#1265);
#1267=ORIENTED_EDGE('',*,*,#239,.F.);
#1268=ORIENTED_EDGE('',*,*,#1257,.T.);
#1269=DIRECTION('',(-0.707094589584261,-0.0052149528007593,-0.707099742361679));
#1270=VECTOR('',#1269,1.);
#1271=CARTESIAN_POINT('',(-4.11117038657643,7.63899752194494,-1.08181516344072));
#1272=LINE('',#1271,#1270);
#1273=CARTESIAN_POINT('',(-5.57144215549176,7.62822774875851,-2.54209757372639));
#1274=VERTEX_POINT('',#1273);
#1275=EDGE_CURVE('E661',#1250,#1274,#1272,.T.);
#1276=ORIENTED_EDGE('',*,*,#1275,.T.);
#1277=DIRECTION('',(-0.00467559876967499,0.999985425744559,-0.0026994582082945));
#1278=VECTOR('',#1277,1.);
#1279=CARTESIAN_POINT('',(-5.5536281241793,3.81828327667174,-2.53181263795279));
#1280=LINE('',#1279,#1278);
#1281=CARTESIAN_POINT('',(-5.5536281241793,3.81828327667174,-2.53181263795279));
#1282=VERTEX_POINT('',#1281);
#1283=EDGE_CURVE('E1641',#1282,#1274,#1280,.T.);
#1284=ORIENTED_EDGE('',*,*,#1283,.F.);
#1285=DIRECTION('',(-0.707094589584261,-0.0052149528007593,-0.707099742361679));
#1286=VECTOR('',#1285,1.);
#1287=CARTESIAN_POINT('',(-4.09335635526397,3.82905304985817,-1.07153022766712));
#1288=LINE('',#1287,#1286);
#1289=EDGE_CURVE('E1635',#238,#1282,#1288,.T.);
#1290=ORIENTED_EDGE('',*,*,#1289,.F.);
#1291=EDGE_LOOP('',(#1267,#1268,#1276,#1284,#1290));
#1292=FACE_BOUND('',#1291,.T.);
#1293=ADVANCED_FACE('F672',(#1292),#1266,.F.);
#1294=CARTESIAN_POINT('',(-5.26152175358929,3.81828327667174,-3.03775571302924));
#1295=DIRECTION('',(0.866012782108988,0.00539891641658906,0.499992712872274));
#1296=DIRECTION('',(0.499999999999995,0.,-0.866025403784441));
#1297=AXIS2_PLACEMENT_3D('',#1294,#1295,#1296);
#1298=PLANE('',#1297);
#1299=DIRECTION('',(0.499999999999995,0.,-0.866025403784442));
#1300=VECTOR('',#1299,1.);
#1301=CARTESIAN_POINT('',(-5.27933578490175,7.62822774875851,-3.04804064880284));
#1302=LINE('',#1301,#1300);
#1303=CARTESIAN_POINT('',(-4.98724215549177,7.62822774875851,-3.55396165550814));
#1304=VERTEX_POINT('',#1303);
#1305=EDGE_CURVE('E658',#1274,#1304,#1302,.T.);
#1306=ORIENTED_EDGE('',*,*,#1305,.T.);
#1307=DIRECTION('',(-0.00467559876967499,0.999985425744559,-0.0026994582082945));
#1308=VECTOR('',#1307,1.);
#1309=CARTESIAN_POINT('',(-4.9694281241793,3.81828327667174,-3.54367671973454));
#1310=LINE('',#1309,#1308);
#1311=CARTESIAN_POINT('',(-4.9694281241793,3.81828327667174,-3.54367671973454));
#1312=VERTEX_POINT('',#1311);
#1313=EDGE_CURVE('E1646',#1312,#1304,#1310,.T.);
#1314=ORIENTED_EDGE('',*,*,#1313,.F.);
#1315=DIRECTION('',(0.499999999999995,0.,-0.866025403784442));
#1316=VECTOR('',#1315,1.);
#1317=CARTESIAN_POINT('',(-5.26152175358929,3.81828327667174,-3.03775571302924));
#1318=LINE('',#1317,#1316);
#1319=EDGE_CURVE('E1676',#1282,#1312,#1318,.T.);
#1320=ORIENTED_EDGE('',*,*,#1319,.F.);
#1321=ORIENTED_EDGE('',*,*,#1283,.T.);
#1322=EDGE_LOOP('',(#1306,#1314,#1320,#1321));
#1323=FACE_BOUND('',#1322,.T.);
#1324=ADVANCED_FACE('F1226',(#1323),#1298,.F.);
#1325=CARTESIAN_POINT('',(-2.97464420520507,3.82905308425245,-3.00918376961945));
#1326=DIRECTION('',(0.258822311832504,-0.0013973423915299,-0.965923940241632));
#1327=DIRECTION('',(-0.965924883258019,0.,-0.258822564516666));
#1328=AXIS2_PLACEMENT_3D('',#1325,#1326,#1327);
#1329=PLANE('',#1328);
#1330=ORIENTED_EDGE('',*,*,#1242,.F.);
#1331=ORIENTED_EDGE('',*,*,#257,.T.);
#1332=DIRECTION('',(-0.965913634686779,-0.0052149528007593,-0.25881200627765));
#1333=VECTOR('',#1332,1.);
#1334=CARTESIAN_POINT('',(-2.97464420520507,3.82905308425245,-3.00918376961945));
#1335=LINE('',#1334,#1333);
#1336=EDGE_CURVE('E663',#247,#1312,#1335,.T.);
#1337=ORIENTED_EDGE('',*,*,#1336,.T.);
#1338=ORIENTED_EDGE('',*,*,#1313,.T.);
#1339=DIRECTION('',(-0.965913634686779,-0.0052149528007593,-0.25881200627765));
#1340=VECTOR('',#1339,1.);
#1341=CARTESIAN_POINT('',(-2.99245823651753,7.63899755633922,-3.01946870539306));
#1342=LINE('',#1341,#1340);
#1343=EDGE_CURVE('E655',#1241,#1304,#1342,.T.);
#1344=ORIENTED_EDGE('',*,*,#1343,.F.);
#1345=EDGE_LOOP('',(#1330,#1331,#1337,#1338,#1344));
#1346=FACE_BOUND('',#1345,.T.);
#1347=ADVANCED_FACE('F675',(#1346),#1329,.T.);
#1348=CARTESIAN_POINT('',(-3.27440134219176,3.83067142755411,-1.89049120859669));
#1349=DIRECTION('',(-0.0046755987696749,0.999985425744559,-0.00269945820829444));
#1350=DIRECTION('',(0.866012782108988,0.00539891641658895,0.499992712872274));
#1351=AXIS2_PLACEMENT_3D('',#1348,#1349,#1350);
#1352=PLANE('',#1351);
#1353=ORIENTED_EDGE('',*,*,#248,.F.);
#1354=ORIENTED_EDGE('',*,*,#1289,.T.);
#1355=ORIENTED_EDGE('',*,*,#1319,.T.);
#1356=ORIENTED_EDGE('',*,*,#1336,.F.);
#1357=EDGE_LOOP('',(#1353,#1354,#1355,#1356));
#1358=FACE_BOUND('',#1357,.T.);
#1359=ADVANCED_FACE('F1244',(#1358),#1352,.F.);
#1360=CARTESIAN_POINT('',(-3.29221537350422,7.64061589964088,-1.90077614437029));
#1361=DIRECTION('',(-0.0046755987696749,0.999985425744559,-0.00269945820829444));
#1362=DIRECTION('',(0.866012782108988,0.00539891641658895,0.499992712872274));
#1363=AXIS2_PLACEMENT_3D('',#1360,#1361,#1362);
#1364=PLANE('',#1363);
#1365=ORIENTED_EDGE('',*,*,#1251,.F.);
#1366=ORIENTED_EDGE('',*,*,#1343,.T.);
#1367=ORIENTED_EDGE('',*,*,#1305,.F.);
#1368=ORIENTED_EDGE('',*,*,#1275,.F.);
#1369=EDGE_LOOP('',(#1365,#1366,#1367,#1368));
#1370=FACE_BOUND('',#1369,.T.);
#1371=ADVANCED_FACE('F623',(#1370),#1364,.T.);
#1372=CARTESIAN_POINT('',(0.0203477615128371,3.85119467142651,0.));
#1373=DIRECTION('',(-0.00539891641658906,0.999985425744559,0.));
#1374=DIRECTION('',(0.,0.,-1.));
#1375=AXIS2_PLACEMENT_3D('',#1372,#1373,#1374);
#1376=ELLIPSE('',#1375,5.08,5.07992596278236);
#1377=DIRECTION('',(-0.00539891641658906,0.999985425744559,0.));
#1378=VECTOR('',#1377,1.);
#1379=SURFACE_OF_LINEAR_EXTRUSION('',#1376,#1378);
#1380=ORIENTED_EDGE('',*,*,#449,.T.);
#1381=DIRECTION('',(-0.00539891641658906,0.999985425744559,0.));
#1382=VECTOR('',#1381,1.);
#1383=CARTESIAN_POINT('',(-4.98325532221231,3.82418024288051,-0.876867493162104));
#1384=LINE('',#1383,#1382);
#1385=CARTESIAN_POINT('',(-5.00382519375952,7.63412471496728,-0.876867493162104));
#1386=VERTEX_POINT('',#1385);
#1387=EDGE_CURVE('E638',#225,#1386,#1384,.T.);
#1388=ORIENTED_EDGE('',*,*,#1387,.T.);
#1389=CARTESIAN_POINT('',(-0.000222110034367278,7.66113914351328,0.));
#1390=DIRECTION('',(-0.00539891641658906,0.999985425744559,0.));
#1391=DIRECTION('',(0.,0.,-1.));
#1392=AXIS2_PLACEMENT_3D('',#1389,#1390,#1391);
#1393=ELLIPSE('',#1392,5.08,5.07992596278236);
#1394=CARTESIAN_POINT('',(-5.00382519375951,7.63412471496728,0.876867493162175));
#1395=VERTEX_POINT('',#1394);
#1396=EDGE_CURVE('E1592',#1386,#1395,#1393,.T.);
#1397=ORIENTED_EDGE('',*,*,#1396,.T.);
#1398=DIRECTION('',(-0.00539891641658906,0.999985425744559,0.));
#1399=VECTOR('',#1398,1.);
#1400=CARTESIAN_POINT('',(-4.9832553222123,3.82418024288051,0.876867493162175));
#1401=LINE('',#1400,#1399);
#1402=EDGE_CURVE('E639',#198,#1395,#1401,.T.);
#1403=ORIENTED_EDGE('',*,*,#1402,.F.);
#1404=EDGE_LOOP('',(#1380,#1388,#1397,#1403));
#1405=FACE_BOUND('',#1404,.T.);
#1406=ADVANCED_FACE('F612',(#1405),#1379,.F.);
#1407=CARTESIAN_POINT('',(-4.08071570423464,3.82905304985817,1.11870577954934));
#1408=DIRECTION('',(0.258815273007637,0.0013973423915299,-0.96592582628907));
#1409=DIRECTION('',(-0.965926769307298,0.,-0.258815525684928));
#1410=AXIS2_PLACEMENT_3D('',#1407,#1408,#1409);
#1411=PLANE('',#1410);
#1412=ORIENTED_EDGE('',*,*,#208,.F.);
#1413=ORIENTED_EDGE('',*,*,#1402,.T.);
#1414=DIRECTION('',(-0.965911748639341,-0.0052149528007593,-0.258819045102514));
#1415=VECTOR('',#1414,1.);
#1416=CARTESIAN_POINT('',(-4.10128557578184,7.63899752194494,1.11870577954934));
#1417=LINE('',#1416,#1415);
#1418=CARTESIAN_POINT('',(-6.09605922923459,7.62822774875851,0.584200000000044));
#1419=VERTEX_POINT('',#1418);
#1420=EDGE_CURVE('E629',#1395,#1419,#1417,.T.);
#1421=ORIENTED_EDGE('',*,*,#1420,.T.);
#1422=DIRECTION('',(-0.00539891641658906,0.999985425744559,0.));
#1423=VECTOR('',#1422,1.);
#1424=CARTESIAN_POINT('',(-6.07548935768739,3.81828327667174,0.584200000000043));
#1425=LINE('',#1424,#1423);
#1426=CARTESIAN_POINT('',(-6.07548935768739,3.81828327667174,0.584200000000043));
#1427=VERTEX_POINT('',#1426);
#1428=EDGE_CURVE('E642',#1427,#1419,#1425,.T.);
#1429=ORIENTED_EDGE('',*,*,#1428,.F.);
#1430=DIRECTION('',(-0.965911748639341,-0.0052149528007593,-0.258819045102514));
#1431=VECTOR('',#1430,1.);
#1432=CARTESIAN_POINT('',(-4.08071570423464,3.82905304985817,1.11870577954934));
#1433=LINE('',#1432,#1431);
#1434=EDGE_CURVE('E636',#207,#1427,#1433,.T.);
#1435=ORIENTED_EDGE('',*,*,#1434,.F.);
#1436=EDGE_LOOP('',(#1412,#1413,#1421,#1429,#1435));
#1437=FACE_BOUND('',#1436,.T.);
#1438=ADVANCED_FACE('F608',(#1437),#1411,.F.);
#1439=CARTESIAN_POINT('',(-6.07548935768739,3.81828327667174,-1.27411799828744E-05));
#1440=DIRECTION('',(0.999985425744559,0.00539891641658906,0.));
#1441=DIRECTION('',(-0.00539891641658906,0.999985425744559,0.));
#1442=AXIS2_PLACEMENT_3D('',#1439,#1440,#1441);
#1443=PLANE('',#1442);
#1444=DIRECTION('',(0.,0.,-1.));
#1445=VECTOR('',#1444,1.);
#1446=CARTESIAN_POINT('',(-6.0960592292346,7.62822774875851,-1.27411799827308E-05));
#1447=LINE('',#1446,#1445);
#1448=CARTESIAN_POINT('',(-6.0960592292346,7.62822774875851,-0.584199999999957));
#1449=VERTEX_POINT('',#1448);
#1450=EDGE_CURVE('E1612',#1419,#1449,#1447,.T.);
#1451=ORIENTED_EDGE('',*,*,#1450,.T.);
#1452=DIRECTION('',(-0.00539891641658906,0.999985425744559,0.));
#1453=VECTOR('',#1452,1.);
#1454=CARTESIAN_POINT('',(-6.0754893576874,3.81828327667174,-0.584199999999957));
#1455=LINE('',#1454,#1453);
#1456=CARTESIAN_POINT('',(-6.0754893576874,3.81828327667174,-0.584199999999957));
#1457=VERTEX_POINT('',#1456);
#1458=EDGE_CURVE('E645',#1457,#1449,#1455,.T.);
#1459=ORIENTED_EDGE('',*,*,#1458,.F.);
#1460=DIRECTION('',(0.,0.,-1.));
#1461=VECTOR('',#1460,1.);
#1462=CARTESIAN_POINT('',(-6.07548935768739,3.81828327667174,-1.27411799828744E-05));
#1463=LINE('',#1462,#1461);
#1464=EDGE_CURVE('E633',#1427,#1457,#1463,.T.);
#1465=ORIENTED_EDGE('',*,*,#1464,.F.);
#1466=ORIENTED_EDGE('',*,*,#1428,.T.);
#1467=EDGE_LOOP('',(#1451,#1459,#1465,#1466));
#1468=FACE_BOUND('',#1467,.T.);
#1469=ADVANCED_FACE('F611',(#1468),#1443,.F.);
#1470=CARTESIAN_POINT('',(-4.08070933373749,3.82905308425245,-1.11870748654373));
#1471=DIRECTION('',(-0.258815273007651,-0.0013973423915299,-0.965925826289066));
#1472=DIRECTION('',(-0.965926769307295,0.,0.258815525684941));
#1473=AXIS2_PLACEMENT_3D('',#1470,#1471,#1472);
#1474=PLANE('',#1473);
#1475=ORIENTED_EDGE('',*,*,#1387,.F.);
#1476=ORIENTED_EDGE('',*,*,#226,.T.);
#1477=DIRECTION('',(-0.965911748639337,-0.0052149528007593,0.258819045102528));
#1478=VECTOR('',#1477,1.);
#1479=CARTESIAN_POINT('',(-4.08070933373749,3.82905308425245,-1.11870748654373));
#1480=LINE('',#1479,#1478);
#1481=EDGE_CURVE('E631',#216,#1457,#1480,.T.);
#1482=ORIENTED_EDGE('',*,*,#1481,.T.);
#1483=ORIENTED_EDGE('',*,*,#1458,.T.);
#1484=DIRECTION('',(-0.965911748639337,-0.0052149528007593,0.258819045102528));
#1485=VECTOR('',#1484,1.);
#1486=CARTESIAN_POINT('',(-4.10127920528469,7.63899755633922,-1.11870748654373));
#1487=LINE('',#1486,#1485);
#1488=EDGE_CURVE('E1610',#1386,#1449,#1487,.T.);
#1489=ORIENTED_EDGE('',*,*,#1488,.F.);
#1490=EDGE_LOOP('',(#1475,#1476,#1482,#1483,#1489));
#1491=FACE_BOUND('',#1490,.T.);
#1492=ADVANCED_FACE('F606',(#1491),#1474,.T.);
#1493=CARTESIAN_POINT('',(-3.78096034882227,3.83067142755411,-1.2741179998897E-05));
#1494=DIRECTION('',(-0.00539891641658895,0.999985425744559,0.));
#1495=DIRECTION('',(0.999985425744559,0.00539891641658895,0.));
#1496=AXIS2_PLACEMENT_3D('',#1493,#1494,#1495);
#1497=PLANE('',#1496);
#1498=ORIENTED_EDGE('',*,*,#217,.F.);
#1499=ORIENTED_EDGE('',*,*,#1434,.T.);
#1500=ORIENTED_EDGE('',*,*,#1464,.T.);
#1501=ORIENTED_EDGE('',*,*,#1481,.F.);
#1502=EDGE_LOOP('',(#1498,#1499,#1500,#1501));
#1503=FACE_BOUND('',#1502,.T.);
#1504=ADVANCED_FACE('F602',(#1503),#1497,.F.);
#1505=CARTESIAN_POINT('',(-3.80153022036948,7.64061589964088,-1.27411799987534E-05));
#1506=DIRECTION('',(-0.00539891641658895,0.999985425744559,0.));
#1507=DIRECTION('',(0.999985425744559,0.00539891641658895,0.));
#1508=AXIS2_PLACEMENT_3D('',#1505,#1506,#1507);
#1509=PLANE('',#1508);
#1510=ORIENTED_EDGE('',*,*,#1396,.F.);
#1511=ORIENTED_EDGE('',*,*,#1488,.T.);
#1512=ORIENTED_EDGE('',*,*,#1450,.F.);
#1513=ORIENTED_EDGE('',*,*,#1420,.F.);
#1514=EDGE_LOOP('',(#1510,#1511,#1512,#1513));
#1515=FACE_BOUND('',#1514,.T.);
#1516=ADVANCED_FACE('F596',(#1515),#1509,.T.);
#1517=CARTESIAN_POINT('',(0.0176216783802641,3.85119467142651,-0.0101738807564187));
#1518=DIRECTION('',(-0.00467559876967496,0.999985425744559,0.00269945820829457));
#1519=DIRECTION('',(-0.500000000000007,0.,-0.866025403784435));
#1520=AXIS2_PLACEMENT_3D('',#1517,#1518,#1519);
#1521=ELLIPSE('',#1520,5.08,5.07992596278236);
#1522=DIRECTION('',(-0.00467559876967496,0.999985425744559,0.00269945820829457));
#1523=VECTOR('',#1522,1.);
#1524=SURFACE_OF_LINEAR_EXTRUSION('',#1521,#1523);
#1525=ORIENTED_EDGE('',*,*,#452,.T.);
#1526=DIRECTION('',(-0.00467559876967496,0.999985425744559,0.00269945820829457));
#1527=VECTOR('',#1526,1.);
#1528=CARTESIAN_POINT('',(-4.75405944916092,3.82418024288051,1.732238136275));
#1529=LINE('',#1528,#1527);
#1530=CARTESIAN_POINT('',(-4.77187348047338,7.63412471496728,1.74252307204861));
#1531=VERTEX_POINT('',#1530);
#1532=EDGE_CURVE('E1606',#194,#1531,#1529,.T.);
#1533=ORIENTED_EDGE('',*,*,#1532,.T.);
#1534=CARTESIAN_POINT('',(-0.000192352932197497,7.66113914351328,0.000111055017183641));
#1535=DIRECTION('',(-0.00467559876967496,0.999985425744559,0.00269945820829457));
#1536=DIRECTION('',(-0.500000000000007,0.,-0.866025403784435));
#1537=AXIS2_PLACEMENT_3D('',#1534,#1535,#1536);
#1538=ELLIPSE('',#1537,5.08,5.07992596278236);
#1539=CARTESIAN_POINT('',(-3.89500598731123,7.63412471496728,3.26130212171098));
#1540=VERTEX_POINT('',#1539);
#1541=EDGE_CURVE('E575',#1531,#1540,#1538,.T.);
#1542=ORIENTED_EDGE('',*,*,#1541,.T.);
#1543=DIRECTION('',(-0.00467559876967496,0.999985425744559,0.00269945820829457));
#1544=VECTOR('',#1543,1.);
#1545=CARTESIAN_POINT('',(-3.87719195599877,3.82418024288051,3.25101718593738));
#1546=LINE('',#1545,#1544);
#1547=EDGE_CURVE('E1587',#167,#1540,#1546,.T.);
#1548=ORIENTED_EDGE('',*,*,#1547,.F.);
#1549=EDGE_LOOP('',(#1525,#1533,#1542,#1548));
#1550=FACE_BOUND('',#1549,.T.);
#1551=ADVANCED_FACE('F591',(#1550),#1524,.F.);
#1552=CARTESIAN_POINT('',(-2.97465057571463,3.82905304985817,3.00918547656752));
#1553=DIRECTION('',(-0.258822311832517,0.0013973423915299,-0.965923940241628));
#1554=DIRECTION('',(-0.965924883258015,0.,0.258822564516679));
#1555=AXIS2_PLACEMENT_3D('',#1552,#1553,#1554);
#1556=PLANE('',#1555);
#1557=ORIENTED_EDGE('',*,*,#177,.F.);
#1558=ORIENTED_EDGE('',*,*,#1547,.T.);
#1559=DIRECTION('',(-0.965913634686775,-0.0052149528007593,0.258812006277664));
#1560=VECTOR('',#1559,1.);
#1561=CARTESIAN_POINT('',(-2.99246460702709,7.63899752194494,3.01947041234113));
#1562=LINE('',#1561,#1560);
#1563=CARTESIAN_POINT('',(-4.98724215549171,7.62822774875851,3.55396165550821));
#1564=VERTEX_POINT('',#1563);
#1565=EDGE_CURVE('E584',#1540,#1564,#1562,.T.);
#1566=ORIENTED_EDGE('',*,*,#1565,.T.);
#1567=DIRECTION('',(-0.00467559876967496,0.999985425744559,0.00269945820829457));
#1568=VECTOR('',#1567,1.);
#1569=CARTESIAN_POINT('',(-4.96942812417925,3.81828327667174,3.54367671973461));
#1570=LINE('',#1569,#1568);
#1571=CARTESIAN_POINT('',(-4.96942812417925,3.81828327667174,3.54367671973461));
#1572=VERTEX_POINT('',#1571);
#1573=EDGE_CURVE('E1596',#1572,#1564,#1570,.T.);
#1574=ORIENTED_EDGE('',*,*,#1573,.F.);
#1575=DIRECTION('',(-0.965913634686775,-0.0052149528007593,0.258812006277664));
#1576=VECTOR('',#1575,1.);
#1577=CARTESIAN_POINT('',(-2.97465057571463,3.82905304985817,3.00918547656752));
#1578=LINE('',#1577,#1576);
#1579=EDGE_CURVE('E1590',#176,#1572,#1578,.T.);
#1580=ORIENTED_EDGE('',*,*,#1579,.F.);
#1581=EDGE_LOOP('',(#1557,#1558,#1566,#1574,#1580));
#1582=FACE_BOUND('',#1581,.T.);
#1583=ADVANCED_FACE('F595',(#1582),#1556,.F.);
#1584=CARTESIAN_POINT('',(-5.26153449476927,3.81828327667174,3.03773364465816));
#1585=DIRECTION('',(0.866012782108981,0.00539891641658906,-0.499992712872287));
#1586=DIRECTION('',(-0.500000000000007,0.,-0.866025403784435));
#1587=AXIS2_PLACEMENT_3D('',#1584,#1585,#1586);
#1588=PLANE('',#1587);
#1589=DIRECTION('',(-0.500000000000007,0.,-0.866025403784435));
#1590=VECTOR('',#1589,1.);
#1591=CARTESIAN_POINT('',(-5.27934852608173,7.62822774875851,3.04801858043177));
#1592=LINE('',#1591,#1590);
#1593=CARTESIAN_POINT('',(-5.57144215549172,7.62822774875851,2.54209757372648));
#1594=VERTEX_POINT('',#1593);
#1595=EDGE_CURVE('E581',#1564,#1594,#1592,.T.);
#1596=ORIENTED_EDGE('',*,*,#1595,.T.);
#1597=DIRECTION('',(-0.00467559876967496,0.999985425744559,0.00269945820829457));
#1598=VECTOR('',#1597,1.);
#1599=CARTESIAN_POINT('',(-5.55362812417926,3.81828327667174,2.53181263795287));
#1600=LINE('',#1599,#1598);
#1601=CARTESIAN_POINT('',(-5.55362812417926,3.81828327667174,2.53181263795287));
#1602=VERTEX_POINT('',#1601);
#1603=EDGE_CURVE('E1601',#1602,#1594,#1600,.T.);
#1604=ORIENTED_EDGE('',*,*,#1603,.F.);
#1605=DIRECTION('',(-0.500000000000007,0.,-0.866025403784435));
#1606=VECTOR('',#1605,1.);
#1607=CARTESIAN_POINT('',(-5.26153449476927,3.81828327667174,3.03773364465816));
#1608=LINE('',#1607,#1606);
#1609=EDGE_CURVE('E1683',#1572,#1602,#1608,.T.);
#1610=ORIENTED_EDGE('',*,*,#1609,.F.);
#1611=ORIENTED_EDGE('',*,*,#1573,.T.);
#1612=EDGE_LOOP('',(#1596,#1604,#1610,#1611));
#1613=FACE_BOUND('',#1612,.T.);
#1614=ADVANCED_FACE('F1315',(#1613),#1588,.F.);
#1615=CARTESIAN_POINT('',(-4.0933516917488,3.82905308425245,1.07152556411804));
#1616=DIRECTION('',(-0.707103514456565,-0.00139734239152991,-0.70710866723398));
#1617=DIRECTION('',(-0.707109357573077,0.,0.707104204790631));
#1618=AXIS2_PLACEMENT_3D('',#1615,#1616,#1617);
#1619=PLANE('',#1618);
#1620=ORIENTED_EDGE('',*,*,#1532,.F.);
#1621=ORIENTED_EDGE('',*,*,#195,.T.);
#1622=DIRECTION('',(-0.707094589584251,-0.0052149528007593,0.707099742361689));
#1623=VECTOR('',#1622,1.);
#1624=CARTESIAN_POINT('',(-4.0933516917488,3.82905308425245,1.07152556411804));
#1625=LINE('',#1624,#1623);
#1626=EDGE_CURVE('E586',#185,#1602,#1625,.T.);
#1627=ORIENTED_EDGE('',*,*,#1626,.T.);
#1628=ORIENTED_EDGE('',*,*,#1603,.T.);
#1629=DIRECTION('',(-0.707094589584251,-0.0052149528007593,0.707099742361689));
#1630=VECTOR('',#1629,1.);
#1631=CARTESIAN_POINT('',(-4.11116572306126,7.63899755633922,1.08181049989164));
#1632=LINE('',#1631,#1630);
#1633=EDGE_CURVE('E578',#1531,#1594,#1632,.T.);
#1634=ORIENTED_EDGE('',*,*,#1633,.F.);
#1635=EDGE_LOOP('',(#1620,#1621,#1627,#1628,#1634));
#1636=FACE_BOUND('',#1635,.T.);
#1637=ADVANCED_FACE('F598',(#1636),#1619,.T.);
#1638=CARTESIAN_POINT('',(-3.27441408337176,3.83067142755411,1.89046914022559));
#1639=DIRECTION('',(-0.00467559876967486,0.999985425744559,0.00269945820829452));
#1640=DIRECTION('',(0.866012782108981,0.00539891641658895,-0.499992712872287));
#1641=AXIS2_PLACEMENT_3D('',#1638,#1639,#1640);
#1642=PLANE('',#1641);
#1643=ORIENTED_EDGE('',*,*,#186,.F.);
#1644=ORIENTED_EDGE('',*,*,#1579,.T.);
#1645=ORIENTED_EDGE('',*,*,#1609,.T.);
#1646=ORIENTED_EDGE('',*,*,#1626,.F.);
#1647=EDGE_LOOP('',(#1643,#1644,#1645,#1646));
#1648=FACE_BOUND('',#1647,.T.);
#1649=ADVANCED_FACE('F1333',(#1648),#1642,.F.);
#1650=CARTESIAN_POINT('',(-3.29222811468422,7.64061589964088,1.90075407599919));
#1651=DIRECTION('',(-0.00467559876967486,0.999985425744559,0.00269945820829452));
#1652=DIRECTION('',(0.866012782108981,0.00539891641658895,-0.499992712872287));
#1653=AXIS2_PLACEMENT_3D('',#1650,#1651,#1652);
#1654=PLANE('',#1653);
#1655=ORIENTED_EDGE('',*,*,#1541,.F.);
#1656=ORIENTED_EDGE('',*,*,#1633,.T.);
#1657=ORIENTED_EDGE('',*,*,#1595,.F.);
#1658=ORIENTED_EDGE('',*,*,#1565,.F.);
#1659=EDGE_LOOP('',(#1655,#1656,#1657,#1658));
#1660=FACE_BOUND('',#1659,.T.);
#1661=ADVANCED_FACE('F546',(#1660),#1654,.T.);
#1662=CARTESIAN_POINT('',(0.0101738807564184,3.85119467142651,-0.0176216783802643));
#1663=DIRECTION('',(-0.00269945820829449,0.999985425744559,0.004675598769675));
#1664=DIRECTION('',(-0.866025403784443,0.,-0.499999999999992));
#1665=AXIS2_PLACEMENT_3D('',#1662,#1663,#1664);
#1666=ELLIPSE('',#1665,5.08,5.07992596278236);
#1667=DIRECTION('',(-0.00269945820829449,0.999985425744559,0.004675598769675));
#1668=VECTOR('',#1667,1.);
#1669=SURFACE_OF_LINEAR_EXTRUSION('',#1666,#1668);
#1670=ORIENTED_EDGE('',*,*,#455,.T.);
#1671=DIRECTION('',(-0.00269945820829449,0.999985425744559,0.004675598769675));
#1672=VECTOR('',#1671,1.);
#1673=CARTESIAN_POINT('',(-3.25101718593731,3.82418024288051,3.87719195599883));
#1674=LINE('',#1673,#1672);
#1675=CARTESIAN_POINT('',(-3.26130212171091,7.63412471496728,3.89500598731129));
#1676=VERTEX_POINT('',#1675);
#1677=EDGE_CURVE('E561',#163,#1676,#1674,.T.);
#1678=ORIENTED_EDGE('',*,*,#1677,.T.);
#1679=CARTESIAN_POINT('',(-0.000111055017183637,7.66113914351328,0.000192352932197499));
#1680=DIRECTION('',(-0.00269945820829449,0.999985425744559,0.004675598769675));
#1681=DIRECTION('',(-0.866025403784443,0.,-0.499999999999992));
#1682=AXIS2_PLACEMENT_3D('',#1679,#1680,#1681);
#1683=ELLIPSE('',#1682,5.08,5.07992596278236);
#1684=CARTESIAN_POINT('',(-1.74252307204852,7.63412471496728,4.77187348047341));
#1685=VERTEX_POINT('',#1684);
#1686=EDGE_CURVE('E1560',#1676,#1685,#1683,.T.);
#1687=ORIENTED_EDGE('',*,*,#1686,.T.);
#1688=DIRECTION('',(-0.00269945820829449,0.999985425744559,0.004675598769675));
#1689=VECTOR('',#1688,1.);
#1690=CARTESIAN_POINT('',(-1.73223813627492,3.82418024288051,4.75405944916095));
#1691=LINE('',#1690,#1689);
#1692=EDGE_CURVE('E562',#136,#1685,#1691,.T.);
#1693=ORIENTED_EDGE('',*,*,#1692,.F.);
#1694=EDGE_LOOP('',(#1670,#1678,#1687,#1693));
#1695=FACE_BOUND('',#1694,.T.);
#1696=ADVANCED_FACE('F535',(#1695),#1669,.F.);
#1697=CARTESIAN_POINT('',(-1.07153022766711,3.82905304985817,4.09335635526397));
#1698=DIRECTION('',(-0.707108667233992,0.0013973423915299,-0.707103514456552));
#1699=DIRECTION('',(-0.707104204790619,0.,0.707109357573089));
#1700=AXIS2_PLACEMENT_3D('',#1697,#1698,#1699);
#1701=PLANE('',#1700);
#1702=ORIENTED_EDGE('',*,*,#146,.F.);
#1703=ORIENTED_EDGE('',*,*,#1692,.T.);
#1704=DIRECTION('',(-0.707099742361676,-0.0052149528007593,0.707094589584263));
#1705=VECTOR('',#1704,1.);
#1706=CARTESIAN_POINT('',(-1.08181516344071,7.63899752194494,4.11117038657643));
#1707=LINE('',#1706,#1705);
#1708=CARTESIAN_POINT('',(-2.54209757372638,7.62822774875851,5.57144215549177));
#1709=VERTEX_POINT('',#1708);
#1710=EDGE_CURVE('E552',#1685,#1709,#1707,.T.);
#1711=ORIENTED_EDGE('',*,*,#1710,.T.);
#1712=DIRECTION('',(-0.00269945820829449,0.999985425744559,0.004675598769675));
#1713=VECTOR('',#1712,1.);
#1714=CARTESIAN_POINT('',(-2.53181263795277,3.81828327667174,5.55362812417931));
#1715=LINE('',#1714,#1713);
#1716=CARTESIAN_POINT('',(-2.53181263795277,3.81828327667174,5.55362812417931));
#1717=VERTEX_POINT('',#1716);
#1718=EDGE_CURVE('E565',#1717,#1709,#1715,.T.);
#1719=ORIENTED_EDGE('',*,*,#1718,.F.);
#1720=DIRECTION('',(-0.707099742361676,-0.0052149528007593,0.707094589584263));
#1721=VECTOR('',#1720,1.);
#1722=CARTESIAN_POINT('',(-1.07153022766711,3.82905304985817,4.09335635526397));
#1723=LINE('',#1722,#1721);
#1724=EDGE_CURVE('E559',#145,#1717,#1723,.T.);
#1725=ORIENTED_EDGE('',*,*,#1724,.F.);
#1726=EDGE_LOOP('',(#1702,#1703,#1711,#1719,#1725));
#1727=FACE_BOUND('',#1726,.T.);
#1728=ADVANCED_FACE('F531',(#1727),#1701,.F.);
#1729=CARTESIAN_POINT('',(-3.03775571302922,3.81828327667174,5.2615217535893));
#1730=DIRECTION('',(0.499992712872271,0.00539891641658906,-0.86601278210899));
#1731=DIRECTION('',(-0.866025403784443,0.,-0.499999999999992));
#1732=AXIS2_PLACEMENT_3D('',#1729,#1730,#1731);
#1733=PLANE('',#1732);
#1734=DIRECTION('',(-0.866025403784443,0.,-0.499999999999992));
#1735=VECTOR('',#1734,1.);
#1736=CARTESIAN_POINT('',(-3.04804064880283,7.62822774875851,5.27933578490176));
#1737=LINE('',#1736,#1735);
#1738=CARTESIAN_POINT('',(-3.55396165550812,7.62822774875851,4.98724215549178));
#1739=VERTEX_POINT('',#1738);
#1740=EDGE_CURVE('E1565',#1709,#1739,#1737,.T.);
#1741=ORIENTED_EDGE('',*,*,#1740,.T.);
#1742=DIRECTION('',(-0.00269945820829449,0.999985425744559,0.004675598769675));
#1743=VECTOR('',#1742,1.);
#1744=CARTESIAN_POINT('',(-3.54367671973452,3.81828327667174,4.96942812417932));
#1745=LINE('',#1744,#1743);
#1746=CARTESIAN_POINT('',(-3.54367671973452,3.81828327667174,4.96942812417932));
#1747=VERTEX_POINT('',#1746);
#1748=EDGE_CURVE('E568',#1747,#1739,#1745,.T.);
#1749=ORIENTED_EDGE('',*,*,#1748,.F.);
#1750=DIRECTION('',(-0.866025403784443,0.,-0.499999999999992));
#1751=VECTOR('',#1750,1.);
#1752=CARTESIAN_POINT('',(-3.03775571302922,3.81828327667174,5.2615217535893));
#1753=LINE('',#1752,#1751);
#1754=EDGE_CURVE('E556',#1717,#1747,#1753,.T.);
#1755=ORIENTED_EDGE('',*,*,#1754,.F.);
#1756=ORIENTED_EDGE('',*,*,#1718,.T.);
#1757=EDGE_LOOP('',(#1741,#1749,#1755,#1756));
#1758=FACE_BOUND('',#1757,.T.);
#1759=ADVANCED_FACE('F534',(#1758),#1733,.F.);
#1760=CARTESIAN_POINT('',(-3.00918376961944,3.82905308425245,2.97464420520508));
#1761=DIRECTION('',(-0.965923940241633,-0.0013973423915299,-0.2588223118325));
#1762=DIRECTION('',(-0.258822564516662,0.,0.96592488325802));
#1763=AXIS2_PLACEMENT_3D('',#1760,#1761,#1762);
#1764=PLANE('',#1763);
#1765=ORIENTED_EDGE('',*,*,#1677,.F.);
#1766=ORIENTED_EDGE('',*,*,#164,.T.);
#1767=DIRECTION('',(-0.258812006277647,-0.0052149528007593,0.965913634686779));
#1768=VECTOR('',#1767,1.);
#1769=CARTESIAN_POINT('',(-3.00918376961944,3.82905308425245,2.97464420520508));
#1770=LINE('',#1769,#1768);
#1771=EDGE_CURVE('E554',#154,#1747,#1770,.T.);
#1772=ORIENTED_EDGE('',*,*,#1771,.T.);
#1773=ORIENTED_EDGE('',*,*,#1748,.T.);
#1774=DIRECTION('',(-0.258812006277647,-0.0052149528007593,0.965913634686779));
#1775=VECTOR('',#1774,1.);
#1776=CARTESIAN_POINT('',(-3.01946870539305,7.63899755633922,2.99245823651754));
#1777=LINE('',#1776,#1775);
#1778=EDGE_CURVE('E1563',#1676,#1739,#1777,.T.);
#1779=ORIENTED_EDGE('',*,*,#1778,.F.);
#1780=EDGE_LOOP('',(#1765,#1766,#1772,#1773,#1779));
#1781=FACE_BOUND('',#1780,.T.);
#1782=ADVANCED_FACE('F529',(#1781),#1764,.T.);
#1783=CARTESIAN_POINT('',(-1.89049120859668,3.83067142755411,3.27440134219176));
#1784=DIRECTION('',(-0.00269945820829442,0.999985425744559,0.00467559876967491));
#1785=DIRECTION('',(0.499992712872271,0.00539891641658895,-0.86601278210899));
#1786=AXIS2_PLACEMENT_3D('',#1783,#1784,#1785);
#1787=PLANE('',#1786);
#1788=ORIENTED_EDGE('',*,*,#155,.F.);
#1789=ORIENTED_EDGE('',*,*,#1724,.T.);
#1790=ORIENTED_EDGE('',*,*,#1754,.T.);
#1791=ORIENTED_EDGE('',*,*,#1771,.F.);
#1792=EDGE_LOOP('',(#1788,#1789,#1790,#1791));
#1793=FACE_BOUND('',#1792,.T.);
#1794=ADVANCED_FACE('F525',(#1793),#1787,.F.);
#1795=CARTESIAN_POINT('',(-1.90077614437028,7.64061589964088,3.29221537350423));
#1796=DIRECTION('',(-0.00269945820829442,0.999985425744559,0.00467559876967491));
#1797=DIRECTION('',(0.499992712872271,0.00539891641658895,-0.86601278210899));
#1798=AXIS2_PLACEMENT_3D('',#1795,#1796,#1797);
#1799=PLANE('',#1798);
#1800=ORIENTED_EDGE('',*,*,#1686,.F.);
#1801=ORIENTED_EDGE('',*,*,#1778,.T.);
#1802=ORIENTED_EDGE('',*,*,#1740,.F.);
#1803=ORIENTED_EDGE('',*,*,#1710,.F.);
#1804=EDGE_LOOP('',(#1800,#1801,#1802,#1803));
#1805=FACE_BOUND('',#1804,.T.);
#1806=ADVANCED_FACE('F519',(#1805),#1799,.T.);
#1807=CARTESIAN_POINT('',(0.,3.85119467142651,-0.0203477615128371));
#1808=DIRECTION('',(0.,0.999985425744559,0.00539891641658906));
#1809=DIRECTION('',(-1.,0.,0.));
#1810=AXIS2_PLACEMENT_3D('',#1807,#1808,#1809);
#1811=ELLIPSE('',#1810,5.08,5.07992596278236);
#1812=DIRECTION('',(0.,0.999985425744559,0.00539891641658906));
#1813=VECTOR('',#1812,1.);
#1814=SURFACE_OF_LINEAR_EXTRUSION('',#1811,#1813);
#1815=ORIENTED_EDGE('',*,*,#458,.T.);
#1816=DIRECTION('',(0.,0.999985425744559,0.00539891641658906));
#1817=VECTOR('',#1816,1.);
#1818=CARTESIAN_POINT('',(-0.876867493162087,3.82418024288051,4.98325532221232));
#1819=LINE('',#1818,#1817);
#1820=CARTESIAN_POINT('',(-0.876867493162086,7.63412471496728,5.00382519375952));
#1821=VERTEX_POINT('',#1820);
#1822=EDGE_CURVE('E1537',#132,#1821,#1819,.T.);
#1823=ORIENTED_EDGE('',*,*,#1822,.T.);
#1824=CARTESIAN_POINT('',(0.,7.66113914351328,0.000222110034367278));
#1825=DIRECTION('',(0.,0.999985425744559,0.00539891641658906));
#1826=DIRECTION('',(-1.,0.,0.));
#1827=AXIS2_PLACEMENT_3D('',#1824,#1825,#1826);
#1828=ELLIPSE('',#1827,5.08,5.07992596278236);
#1829=CARTESIAN_POINT('',(0.876867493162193,7.63412471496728,5.0038251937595));
#1830=VERTEX_POINT('',#1829);
#1831=EDGE_CURVE('E498',#1821,#1830,#1828,.T.);
#1832=ORIENTED_EDGE('',*,*,#1831,.T.);
#1833=DIRECTION('',(0.,0.999985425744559,0.00539891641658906));
#1834=VECTOR('',#1833,1.);
#1835=CARTESIAN_POINT('',(0.876867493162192,3.82418024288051,4.9832553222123));
#1836=LINE('',#1835,#1834);
#1837=EDGE_CURVE('E1549',#105,#1830,#1836,.T.);
#1838=ORIENTED_EDGE('',*,*,#1837,.F.);
#1839=EDGE_LOOP('',(#1815,#1823,#1832,#1838));
#1840=FACE_BOUND('',#1839,.T.);
#1841=ADVANCED_FACE('F514',(#1840),#1814,.F.);
#1842=CARTESIAN_POINT('',(1.11870577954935,3.82905304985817,4.08071570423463));
#1843=DIRECTION('',(-0.965925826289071,0.0013973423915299,-0.258815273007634));
#1844=DIRECTION('',(-0.258815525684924,0.,0.965926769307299));
#1845=AXIS2_PLACEMENT_3D('',#1842,#1843,#1844);
#1846=PLANE('',#1845);
#1847=ORIENTED_EDGE('',*,*,#115,.F.);
#1848=ORIENTED_EDGE('',*,*,#1837,.T.);
#1849=DIRECTION('',(-0.258819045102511,-0.0052149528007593,0.965911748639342));
#1850=VECTOR('',#1849,1.);
#1851=CARTESIAN_POINT('',(1.11870577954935,7.63899752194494,4.10128557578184));
#1852=LINE('',#1851,#1850);
#1853=CARTESIAN_POINT('',(0.584200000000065,7.62822774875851,6.09605922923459));
#1854=VERTEX_POINT('',#1853);
#1855=EDGE_CURVE('E507',#1830,#1854,#1852,.T.);
#1856=ORIENTED_EDGE('',*,*,#1855,.T.);
#1857=DIRECTION('',(0.,0.999985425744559,0.00539891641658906));
#1858=VECTOR('',#1857,1.);
#1859=CARTESIAN_POINT('',(0.584200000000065,3.81828327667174,6.07548935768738));
#1860=LINE('',#1859,#1858);
#1861=CARTESIAN_POINT('',(0.584200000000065,3.81828327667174,6.07548935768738));
#1862=VERTEX_POINT('',#1861);
#1863=EDGE_CURVE('E1543',#1862,#1854,#1860,.T.);
#1864=ORIENTED_EDGE('',*,*,#1863,.F.);
#1865=DIRECTION('',(-0.258819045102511,-0.0052149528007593,0.965911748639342));
#1866=VECTOR('',#1865,1.);
#1867=CARTESIAN_POINT('',(1.11870577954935,3.82905304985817,4.08071570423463));
#1868=LINE('',#1867,#1866);
#1869=EDGE_CURVE('E1556',#114,#1862,#1868,.T.);
#1870=ORIENTED_EDGE('',*,*,#1869,.F.);
#1871=EDGE_LOOP('',(#1847,#1848,#1856,#1864,#1870));
#1872=FACE_BOUND('',#1871,.T.);
#1873=ADVANCED_FACE('F518',(#1872),#1846,.F.);
#1874=CARTESIAN_POINT('',(-1.27411799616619E-05,3.81828327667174,6.07548935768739));
#1875=DIRECTION('',(0.,0.00539891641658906,-0.999985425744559));
#1876=DIRECTION('',(0.,0.999985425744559,0.00539891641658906));
#1877=AXIS2_PLACEMENT_3D('',#1874,#1875,#1876);
#1878=PLANE('',#1877);
#1879=DIRECTION('',(-1.,0.,0.));
#1880=VECTOR('',#1879,1.);
#1881=CARTESIAN_POINT('',(-1.27411799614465E-05,7.62822774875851,6.0960592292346));
#1882=LINE('',#1881,#1880);
#1883=CARTESIAN_POINT('',(-0.584199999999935,7.62822774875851,6.0960592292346));
#1884=VERTEX_POINT('',#1883);
#1885=EDGE_CURVE('E504',#1854,#1884,#1882,.T.);
#1886=ORIENTED_EDGE('',*,*,#1885,.T.);
#1887=DIRECTION('',(0.,0.999985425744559,0.00539891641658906));
#1888=VECTOR('',#1887,1.);
#1889=CARTESIAN_POINT('',(-0.584199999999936,3.81828327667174,6.0754893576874));
#1890=LINE('',#1889,#1888);
#1891=CARTESIAN_POINT('',(-0.584199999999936,3.81828327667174,6.0754893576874));
#1892=VERTEX_POINT('',#1891);
#1893=EDGE_CURVE('E1539',#1892,#1884,#1890,.T.);
#1894=ORIENTED_EDGE('',*,*,#1893,.F.);
#1895=DIRECTION('',(-1.,0.,0.));
#1896=VECTOR('',#1895,1.);
#1897=CARTESIAN_POINT('',(-1.27411799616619E-05,3.81828327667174,6.07548935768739));
#1898=LINE('',#1897,#1896);
#1899=EDGE_CURVE('E1547',#1862,#1892,#1898,.T.);
#1900=ORIENTED_EDGE('',*,*,#1899,.F.);
#1901=ORIENTED_EDGE('',*,*,#1863,.T.);
#1902=EDGE_LOOP('',(#1886,#1894,#1900,#1901));
#1903=FACE_BOUND('',#1902,.T.);
#1904=ADVANCED_FACE('F1404',(#1903),#1878,.F.);
#1905=CARTESIAN_POINT('',(-1.11870748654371,3.82905308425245,4.08070933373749));
#1906=DIRECTION('',(-0.965925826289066,-0.0013973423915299,0.258815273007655));
#1907=DIRECTION('',(0.258815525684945,0.,0.965926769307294));
#1908=AXIS2_PLACEMENT_3D('',#1905,#1906,#1907);
#1909=PLANE('',#1908);
#1910=ORIENTED_EDGE('',*,*,#1822,.F.);
#1911=ORIENTED_EDGE('',*,*,#133,.T.);
#1912=DIRECTION('',(0.258819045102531,-0.0052149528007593,0.965911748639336));
#1913=VECTOR('',#1912,1.);
#1914=CARTESIAN_POINT('',(-1.11870748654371,3.82905308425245,4.08070933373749));
#1915=LINE('',#1914,#1913);
#1916=EDGE_CURVE('E509',#123,#1892,#1915,.T.);
#1917=ORIENTED_EDGE('',*,*,#1916,.T.);
#1918=ORIENTED_EDGE('',*,*,#1893,.T.);
#1919=DIRECTION('',(0.258819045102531,-0.0052149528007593,0.965911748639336));
#1920=VECTOR('',#1919,1.);
#1921=CARTESIAN_POINT('',(-1.11870748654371,7.63899755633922,4.1012792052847));
#1922=LINE('',#1921,#1920);
#1923=EDGE_CURVE('E501',#1821,#1884,#1922,.T.);
#1924=ORIENTED_EDGE('',*,*,#1923,.F.);
#1925=EDGE_LOOP('',(#1910,#1911,#1917,#1918,#1924));
#1926=FACE_BOUND('',#1925,.T.);
#1927=ADVANCED_FACE('F521',(#1926),#1909,.T.);
#1928=CARTESIAN_POINT('',(-1.27411799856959E-05,3.83067142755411,3.78096034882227));
#1929=DIRECTION('',(0.,0.999985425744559,0.00539891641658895));
#1930=DIRECTION('',(0.,0.00539891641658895,-0.999985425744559));
#1931=AXIS2_PLACEMENT_3D('',#1928,#1929,#1930);
#1932=PLANE('',#1931);
#1933=ORIENTED_EDGE('',*,*,#124,.F.);
#1934=ORIENTED_EDGE('',*,*,#1869,.T.);
#1935=ORIENTED_EDGE('',*,*,#1899,.T.);
#1936=ORIENTED_EDGE('',*,*,#1916,.F.);
#1937=EDGE_LOOP('',(#1933,#1934,#1935,#1936));
#1938=FACE_BOUND('',#1937,.T.);
#1939=ADVANCED_FACE('F1422',(#1938),#1932,.F.);
#1940=CARTESIAN_POINT('',(-1.27411799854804E-05,7.64061589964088,3.80153022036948));
#1941=DIRECTION('',(0.,0.999985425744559,0.00539891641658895));
#1942=DIRECTION('',(0.,0.00539891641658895,-0.999985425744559));
#1943=AXIS2_PLACEMENT_3D('',#1940,#1941,#1942);
#1944=PLANE('',#1943);
#1945=ORIENTED_EDGE('',*,*,#1831,.F.);
#1946=ORIENTED_EDGE('',*,*,#1923,.T.);
#1947=ORIENTED_EDGE('',*,*,#1885,.F.);
#1948=ORIENTED_EDGE('',*,*,#1855,.F.);
#1949=EDGE_LOOP('',(#1945,#1946,#1947,#1948));
#1950=FACE_BOUND('',#1949,.T.);
#1951=ADVANCED_FACE('F469',(#1950),#1944,.T.);
#1952=CARTESIAN_POINT('',(-0.0101738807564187,3.85119467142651,-0.0176216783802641));
#1953=DIRECTION('',(0.00269945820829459,0.999985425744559,0.00467559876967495));
#1954=DIRECTION('',(-0.866025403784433,0.,0.50000000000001));
#1955=AXIS2_PLACEMENT_3D('',#1952,#1953,#1954);
#1956=ELLIPSE('',#1955,5.08,5.07992596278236);
#1957=DIRECTION('',(0.00269945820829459,0.999985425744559,0.00467559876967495));
#1958=VECTOR('',#1957,1.);
#1959=SURFACE_OF_LINEAR_EXTRUSION('',#1956,#1958);
#1960=ORIENTED_EDGE('',*,*,#461,.T.);
#1961=DIRECTION('',(0.00269945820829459,0.999985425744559,0.00467559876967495));
#1962=VECTOR('',#1961,1.);
#1963=CARTESIAN_POINT('',(1.73223813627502,3.82418024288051,4.75405944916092));
#1964=LINE('',#1963,#1962);
#1965=CARTESIAN_POINT('',(1.74252307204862,7.63412471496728,4.77187348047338));
#1966=VERTEX_POINT('',#1965);
#1967=EDGE_CURVE('E484',#101,#1966,#1964,.T.);
#1968=ORIENTED_EDGE('',*,*,#1967,.T.);
#1969=CARTESIAN_POINT('',(0.000111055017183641,7.66113914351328,0.000192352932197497));
#1970=DIRECTION('',(0.00269945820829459,0.999985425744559,0.00467559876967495));
#1971=DIRECTION('',(-0.866025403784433,0.,0.50000000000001));
#1972=AXIS2_PLACEMENT_3D('',#1969,#1970,#1971);
#1973=ELLIPSE('',#1972,5.08,5.07992596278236);
#1974=CARTESIAN_POINT('',(3.26130212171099,7.63412471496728,3.89500598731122));
#1975=VERTEX_POINT('',#1974);
#1976=EDGE_CURVE('E935',#1966,#1975,#1973,.T.);
#1977=ORIENTED_EDGE('',*,*,#1976,.T.);
#1978=DIRECTION('',(0.00269945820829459,0.999985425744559,0.00467559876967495));
#1979=VECTOR('',#1978,1.);
#1980=CARTESIAN_POINT('',(3.25101718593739,3.82418024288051,3.87719195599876));
#1981=LINE('',#1980,#1979);
#1982=EDGE_CURVE('E485',#74,#1975,#1981,.T.);
#1983=ORIENTED_EDGE('',*,*,#1982,.F.);
#1984=EDGE_LOOP('',(#1960,#1968,#1977,#1983));
#1985=FACE_BOUND('',#1984,.T.);
#1986=ADVANCED_FACE('F458',(#1985),#1959,.F.);
#1987=CARTESIAN_POINT('',(3.00918547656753,3.82905304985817,2.97465057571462));
#1988=DIRECTION('',(-0.965923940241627,0.0013973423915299,0.258822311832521));
#1989=DIRECTION('',(0.258822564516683,0.,0.965924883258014));
#1990=AXIS2_PLACEMENT_3D('',#1987,#1988,#1989);
#1991=PLANE('',#1990);
#1992=ORIENTED_EDGE('',*,*,#84,.F.);
#1993=ORIENTED_EDGE('',*,*,#1982,.T.);
#1994=DIRECTION('',(0.258812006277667,-0.0052149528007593,0.965913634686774));
#1995=VECTOR('',#1994,1.);
#1996=CARTESIAN_POINT('',(3.01947041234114,7.63899752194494,2.99246460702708));
#1997=LINE('',#1996,#1995);
#1998=CARTESIAN_POINT('',(3.55396165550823,7.62822774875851,4.9872421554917));
#1999=VERTEX_POINT('',#1998);
#2000=EDGE_CURVE('E475',#1975,#1999,#1997,.T.);
#2001=ORIENTED_EDGE('',*,*,#2000,.T.);
#2002=DIRECTION('',(0.00269945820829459,0.999985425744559,0.00467559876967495));
#2003=VECTOR('',#2002,1.);
#2004=CARTESIAN_POINT('',(3.54367671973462,3.81828327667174,4.96942812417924));
#2005=LINE('',#2004,#2003);
#2006=CARTESIAN_POINT('',(3.54367671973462,3.81828327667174,4.96942812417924));
#2007=VERTEX_POINT('',#2006);
#2008=EDGE_CURVE('E488',#2007,#1999,#2005,.T.);
#2009=ORIENTED_EDGE('',*,*,#2008,.F.);
#2010=DIRECTION('',(0.258812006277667,-0.0052149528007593,0.965913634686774));
#2011=VECTOR('',#2010,1.);
#2012=CARTESIAN_POINT('',(3.00918547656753,3.82905304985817,2.97465057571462));
#2013=LINE('',#2012,#2011);
#2014=EDGE_CURVE('E482',#83,#2007,#2013,.T.);
#2015=ORIENTED_EDGE('',*,*,#2014,.F.);
#2016=EDGE_LOOP('',(#1992,#1993,#2001,#2009,#2015));
#2017=FACE_BOUND('',#2016,.T.);
#2018=ADVANCED_FACE('F454',(#2017),#1991,.F.);
#2019=CARTESIAN_POINT('',(3.03773364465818,3.81828327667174,5.26153449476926));
#2020=DIRECTION('',(-0.49999271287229,0.00539891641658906,-0.86601278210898));
#2021=DIRECTION('',(-0.866025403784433,0.,0.50000000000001));
#2022=AXIS2_PLACEMENT_3D('',#2019,#2020,#2021);
#2023=PLANE('',#2022);
#2024=DIRECTION('',(-0.866025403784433,0.,0.50000000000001));
#2025=VECTOR('',#2024,1.);
#2026=CARTESIAN_POINT('',(3.04801858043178,7.62822774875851,5.27934852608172));
#2027=LINE('',#2026,#2025);
#2028=CARTESIAN_POINT('',(2.54209757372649,7.62822774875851,5.57144215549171));
#2029=VERTEX_POINT('',#2028);
#2030=EDGE_CURVE('E931',#1999,#2029,#2027,.T.);
#2031=ORIENTED_EDGE('',*,*,#2030,.T.);
#2032=DIRECTION('',(0.00269945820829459,0.999985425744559,0.00467559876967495));
#2033=VECTOR('',#2032,1.);
#2034=CARTESIAN_POINT('',(2.53181263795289,3.81828327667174,5.55362812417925));
#2035=LINE('',#2034,#2033);
#2036=CARTESIAN_POINT('',(2.53181263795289,3.81828327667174,5.55362812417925));
#2037=VERTEX_POINT('',#2036);
#2038=EDGE_CURVE('E491',#2037,#2029,#2035,.T.);
#2039=ORIENTED_EDGE('',*,*,#2038,.F.);
#2040=DIRECTION('',(-0.866025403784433,0.,0.50000000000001));
#2041=VECTOR('',#2040,1.);
#2042=CARTESIAN_POINT('',(3.03773364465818,3.81828327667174,5.26153449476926));
#2043=LINE('',#2042,#2041);
#2044=EDGE_CURVE('E479',#2007,#2037,#2043,.T.);
#2045=ORIENTED_EDGE('',*,*,#2044,.F.);
#2046=ORIENTED_EDGE('',*,*,#2008,.T.);
#2047=EDGE_LOOP('',(#2031,#2039,#2045,#2046));
#2048=FACE_BOUND('',#2047,.T.);
#2049=ADVANCED_FACE('F457',(#2048),#2023,.F.);
#2050=CARTESIAN_POINT('',(1.07152556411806,3.82905308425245,4.09335169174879));
#2051=DIRECTION('',(-0.707108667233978,-0.00139734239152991,0.707103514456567));
#2052=DIRECTION('',(0.707104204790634,0.,0.707109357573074));
#2053=AXIS2_PLACEMENT_3D('',#2050,#2051,#2052);
#2054=PLANE('',#2053);
#2055=ORIENTED_EDGE('',*,*,#1967,.F.);
#2056=ORIENTED_EDGE('',*,*,#102,.T.);
#2057=DIRECTION('',(0.707099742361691,-0.0052149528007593,0.707094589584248));
#2058=VECTOR('',#2057,1.);
#2059=CARTESIAN_POINT('',(1.07152556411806,3.82905308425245,4.09335169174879));
#2060=LINE('',#2059,#2058);
#2061=EDGE_CURVE('E477',#92,#2037,#2060,.T.);
#2062=ORIENTED_EDGE('',*,*,#2061,.T.);
#2063=ORIENTED_EDGE('',*,*,#2038,.T.);
#2064=DIRECTION('',(0.707099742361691,-0.0052149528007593,0.707094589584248));
#2065=VECTOR('',#2064,1.);
#2066=CARTESIAN_POINT('',(1.08181049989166,7.63899755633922,4.11116572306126));
#2067=LINE('',#2066,#2065);
#2068=EDGE_CURVE('E933',#1966,#2029,#2067,.T.);
#2069=ORIENTED_EDGE('',*,*,#2068,.F.);
#2070=EDGE_LOOP('',(#2055,#2056,#2062,#2063,#2069));
#2071=FACE_BOUND('',#2070,.T.);
#2072=ADVANCED_FACE('F452',(#2071),#2054,.T.);
#2073=CARTESIAN_POINT('',(1.8904691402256,3.83067142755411,3.27441408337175));
#2074=DIRECTION('',(0.00269945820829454,0.999985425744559,0.00467559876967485));
#2075=DIRECTION('',(-0.49999271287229,0.00539891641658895,-0.86601278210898));
#2076=AXIS2_PLACEMENT_3D('',#2073,#2074,#2075);
#2077=PLANE('',#2076);
#2078=ORIENTED_EDGE('',*,*,#93,.F.);
#2079=ORIENTED_EDGE('',*,*,#2014,.T.);
#2080=ORIENTED_EDGE('',*,*,#2044,.T.);
#2081=ORIENTED_EDGE('',*,*,#2061,.F.);
#2082=EDGE_LOOP('',(#2078,#2079,#2080,#2081));
#2083=FACE_BOUND('',#2082,.T.);
#2084=ADVANCED_FACE('F448',(#2083),#2077,.F.);
#2085=CARTESIAN_POINT('',(1.9007540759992,7.64061589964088,3.29222811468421));
#2086=DIRECTION('',(0.00269945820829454,0.999985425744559,0.00467559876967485));
#2087=DIRECTION('',(-0.49999271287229,0.00539891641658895,-0.86601278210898));
#2088=AXIS2_PLACEMENT_3D('',#2085,#2086,#2087);
#2089=PLANE('',#2088);
#2090=ORIENTED_EDGE('',*,*,#1976,.F.);
#2091=ORIENTED_EDGE('',*,*,#2068,.T.);
#2092=ORIENTED_EDGE('',*,*,#2030,.F.);
#2093=ORIENTED_EDGE('',*,*,#2000,.F.);
#2094=EDGE_LOOP('',(#2090,#2091,#2092,#2093));
#2095=FACE_BOUND('',#2094,.T.);
#2096=ADVANCED_FACE('F444',(#2095),#2089,.T.);
#2097=CARTESIAN_POINT('',(-0.0176216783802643,3.85119467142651,-0.0101738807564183));
#2098=DIRECTION('',(0.00467559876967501,0.999985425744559,0.00269945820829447));
#2099=DIRECTION('',(-0.499999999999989,0.,0.866025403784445));
#2100=AXIS2_PLACEMENT_3D('',#2097,#2098,#2099);
#2101=ELLIPSE('',#2100,5.08,5.07992596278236);
#2102=DIRECTION('',(0.00467559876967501,0.999985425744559,0.00269945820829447));
#2103=VECTOR('',#2102,1.);
#2104=SURFACE_OF_LINEAR_EXTRUSION('',#2101,#2103);
#2105=ORIENTED_EDGE('',*,*,#464,.T.);
#2106=DIRECTION('',(0.00467559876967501,0.999985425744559,0.00269945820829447));
#2107=VECTOR('',#2106,1.);
#2108=CARTESIAN_POINT('',(3.87719195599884,3.82418024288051,3.25101718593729));
#2109=LINE('',#2108,#2107);
#2110=CARTESIAN_POINT('',(3.8950059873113,7.63412471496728,3.2613021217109));
#2111=VERTEX_POINT('',#2110);
#2112=EDGE_CURVE('E408',#70,#2111,#2109,.T.);
#2113=ORIENTED_EDGE('',*,*,#2112,.T.);
#2114=CARTESIAN_POINT('',(0.000192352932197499,7.66113914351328,0.000111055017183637));
#2115=DIRECTION('',(0.00467559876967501,0.999985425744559,0.00269945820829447));
#2116=DIRECTION('',(-0.499999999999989,0.,0.866025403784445));
#2117=AXIS2_PLACEMENT_3D('',#2114,#2115,#2116);
#2118=ELLIPSE('',#2117,5.08,5.07992596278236);
#2119=CARTESIAN_POINT('',(4.77187348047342,7.63412471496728,1.7425230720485));
#2120=VERTEX_POINT('',#2119);
#2121=EDGE_CURVE('E412',#2111,#2120,#2118,.T.);
#2122=ORIENTED_EDGE('',*,*,#2121,.T.);
#2123=DIRECTION('',(0.00467559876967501,0.999985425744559,0.00269945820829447));
#2124=VECTOR('',#2123,1.);
#2125=CARTESIAN_POINT('',(4.75405944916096,3.82418024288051,1.7322381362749));
#2126=LINE('',#2125,#2124);
#2127=EDGE_CURVE('E942',#43,#2120,#2126,.T.);
#2128=ORIENTED_EDGE('',*,*,#2127,.F.);
#2129=EDGE_LOOP('',(#2105,#2113,#2122,#2128));
#2130=FACE_BOUND('',#2129,.T.);
#2131=ADVANCED_FACE('F410',(#2130),#2104,.F.);
#2132=CARTESIAN_POINT('',(4.09335635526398,3.82905304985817,1.07153022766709));
#2133=DIRECTION('',(-0.70710351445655,0.0013973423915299,0.707108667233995));
#2134=DIRECTION('',(0.707109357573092,0.,0.707104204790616));
#2135=AXIS2_PLACEMENT_3D('',#2132,#2133,#2134);
#2136=PLANE('',#2135);
#2137=ORIENTED_EDGE('',*,*,#53,.F.);
#2138=ORIENTED_EDGE('',*,*,#2127,.T.);
#2139=DIRECTION('',(0.707094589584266,-0.0052149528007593,0.707099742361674));
#2140=VECTOR('',#2139,1.);
#2141=CARTESIAN_POINT('',(4.11117038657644,7.63899752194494,1.0818151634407));
#2142=LINE('',#2141,#2140);
#2143=CARTESIAN_POINT('',(5.57144215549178,7.62822774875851,2.54209757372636));
#2144=VERTEX_POINT('',#2143);
#2145=EDGE_CURVE('E425',#2120,#2144,#2142,.T.);
#2146=ORIENTED_EDGE('',*,*,#2145,.T.);
#2147=DIRECTION('',(0.00467559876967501,0.999985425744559,0.00269945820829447));
#2148=VECTOR('',#2147,1.);
#2149=CARTESIAN_POINT('',(5.55362812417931,3.81828327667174,2.53181263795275));
#2150=LINE('',#2149,#2148);
#2151=CARTESIAN_POINT('',(5.55362812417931,3.81828327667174,2.53181263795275));
#2152=VERTEX_POINT('',#2151);
#2153=EDGE_CURVE('E945',#2152,#2144,#2150,.T.);
#2154=ORIENTED_EDGE('',*,*,#2153,.F.);
#2155=DIRECTION('',(0.707094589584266,-0.0052149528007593,0.707099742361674));
#2156=VECTOR('',#2155,1.);
#2157=CARTESIAN_POINT('',(4.09335635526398,3.82905304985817,1.07153022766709));
#2158=LINE('',#2157,#2156);
#2159=EDGE_CURVE('E417',#52,#2152,#2158,.T.);
#2160=ORIENTED_EDGE('',*,*,#2159,.F.);
#2161=EDGE_LOOP('',(#2137,#2138,#2146,#2154,#2160));
#2162=FACE_BOUND('',#2161,.T.);
#2163=ADVANCED_FACE('F443',(#2162),#2136,.F.);
#2164=CARTESIAN_POINT('',(5.26152175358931,3.81828327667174,3.0377557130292));
#2165=DIRECTION('',(-0.866012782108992,0.00539891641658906,-0.499992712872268));
#2166=DIRECTION('',(-0.499999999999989,0.,0.866025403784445));
#2167=AXIS2_PLACEMENT_3D('',#2164,#2165,#2166);
#2168=PLANE('',#2167);
#2169=DIRECTION('',(-0.499999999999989,0.,0.866025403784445));
#2170=VECTOR('',#2169,1.);
#2171=CARTESIAN_POINT('',(5.27933578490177,7.62822774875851,3.04804064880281));
#2172=LINE('',#2171,#2170);
#2173=CARTESIAN_POINT('',(4.98724215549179,7.62822774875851,3.5539616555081));
#2174=VERTEX_POINT('',#2173);
#2175=EDGE_CURVE('E430',#2144,#2174,#2172,.T.);
#2176=ORIENTED_EDGE('',*,*,#2175,.T.);
#2177=DIRECTION('',(0.00467559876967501,0.999985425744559,0.00269945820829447));
#2178=VECTOR('',#2177,1.);
#2179=CARTESIAN_POINT('',(4.96942812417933,3.81828327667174,3.5436767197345));
#2180=LINE('',#2179,#2178);
#2181=CARTESIAN_POINT('',(4.96942812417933,3.81828327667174,3.5436767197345));
#2182=VERTEX_POINT('',#2181);
#2183=EDGE_CURVE('E416',#2182,#2174,#2180,.T.);
#2184=ORIENTED_EDGE('',*,*,#2183,.F.);
#2185=DIRECTION('',(-0.499999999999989,0.,0.866025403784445));
#2186=VECTOR('',#2185,1.);
#2187=CARTESIAN_POINT('',(5.26152175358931,3.81828327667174,3.0377557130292));
#2188=LINE('',#2187,#2186);
#2189=EDGE_CURVE('E949',#2152,#2182,#2188,.T.);
#2190=ORIENTED_EDGE('',*,*,#2189,.F.);
#2191=ORIENTED_EDGE('',*,*,#2153,.T.);
#2192=EDGE_LOOP('',(#2176,#2184,#2190,#2191));
#2193=FACE_BOUND('',#2192,.T.);
#2194=ADVANCED_FACE('F959',(#2193),#2168,.F.);
#2195=CARTESIAN_POINT('',(2.97464420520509,3.82905308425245,3.00918376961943));
#2196=DIRECTION('',(-0.258822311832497,-0.00139734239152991,0.965923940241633));
#2197=DIRECTION('',(0.96592488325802,0.,0.258822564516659));
#2198=AXIS2_PLACEMENT_3D('',#2195,#2196,#2197);
#2199=PLANE('',#2198);
#2200=ORIENTED_EDGE('',*,*,#2112,.F.);
#2201=ORIENTED_EDGE('',*,*,#71,.T.);
#2202=DIRECTION('',(0.96591363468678,-0.0052149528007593,0.258812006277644));
#2203=VECTOR('',#2202,1.);
#2204=CARTESIAN_POINT('',(2.97464420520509,3.82905308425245,3.00918376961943));
#2205=LINE('',#2204,#2203);
#2206=EDGE_CURVE('E435',#61,#2182,#2205,.T.);
#2207=ORIENTED_EDGE('',*,*,#2206,.T.);
#2208=ORIENTED_EDGE('',*,*,#2183,.T.);
#2209=DIRECTION('',(0.96591363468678,-0.0052149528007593,0.258812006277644));
#2210=VECTOR('',#2209,1.);
#2211=CARTESIAN_POINT('',(2.99245823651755,7.63899755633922,3.01946870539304));
#2212=LINE('',#2211,#2210);
#2213=EDGE_CURVE('E424',#2111,#2174,#2212,.T.);
#2214=ORIENTED_EDGE('',*,*,#2213,.F.);
#2215=EDGE_LOOP('',(#2200,#2201,#2207,#2208,#2214));
#2216=FACE_BOUND('',#2215,.T.);
#2217=ADVANCED_FACE('F427',(#2216),#2199,.T.);
#2218=CARTESIAN_POINT('',(3.27440134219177,3.83067142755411,1.89049120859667));
#2219=DIRECTION('',(0.00467559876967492,0.999985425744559,0.00269945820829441));
#2220=DIRECTION('',(-0.866012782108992,0.00539891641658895,-0.499992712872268));
#2221=AXIS2_PLACEMENT_3D('',#2218,#2219,#2220);
#2222=PLANE('',#2221);
#2223=ORIENTED_EDGE('',*,*,#62,.F.);
#2224=ORIENTED_EDGE('',*,*,#2159,.T.);
#2225=ORIENTED_EDGE('',*,*,#2189,.T.);
#2226=ORIENTED_EDGE('',*,*,#2206,.F.);
#2227=EDGE_LOOP('',(#2223,#2224,#2225,#2226));
#2228=FACE_BOUND('',#2227,.T.);
#2229=ADVANCED_FACE('F954',(#2228),#2222,.F.);
#2230=CARTESIAN_POINT('',(3.29221537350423,7.64061589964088,1.90077614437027));
#2231=DIRECTION('',(0.00467559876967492,0.999985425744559,0.00269945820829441));
#2232=DIRECTION('',(-0.866012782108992,0.00539891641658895,-0.499992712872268));
#2233=AXIS2_PLACEMENT_3D('',#2230,#2231,#2232);
#2234=PLANE('',#2233);
#2235=ORIENTED_EDGE('',*,*,#2121,.F.);
#2236=ORIENTED_EDGE('',*,*,#2213,.T.);
#2237=ORIENTED_EDGE('',*,*,#2175,.F.);
#2238=ORIENTED_EDGE('',*,*,#2145,.F.);
#2239=EDGE_LOOP('',(#2235,#2236,#2237,#2238));
#2240=FACE_BOUND('',#2239,.T.);
#2241=ADVANCED_FACE('F422',(#2240),#2234,.T.);
#2242=CLOSED_SHELL('',(#414,#469,#489,#501,#536,#568,#599,#622,#634,#646,#681,#713,#744,#767,
#779,#791,#826,#858,#889,#912,#924,#936,#971,#1003,#1034,#1057,#1069,#1081,#1116,#1148,#1179,
#1202,#1214,#1226,#1261,#1293,#1324,#1347,#1359,#1371,#1406,#1438,#1469,#1492,#1504,#1516,#1551,
#1583,#1614,#1637,#1649,#1661,#1696,#1728,#1759,#1782,#1794,#1806,#1841,#1873,#1904,#1927,#1939,
#1951,#1986,#2018,#2049,#2072,#2084,#2096,#2131,#2163,#2194,#2217,#2229,#2241));
#2243=MANIFOLD_SOLID_BREP('B2',#2242);
#2244=ADVANCED_BREP_SHAPE_REPRESENTATION('',(#18,#2243),#14);
#2245=SHAPE_DEFINITION_REPRESENTATION(#9,#2244);
ENDSEC;
END-ISO-10303-21;
